VERSION 5.7 ;
  NOWIREEXTENSIONATPIN ON ;
  DIVIDERCHAR "/" ;
  BUSBITCHARS "[]" ;
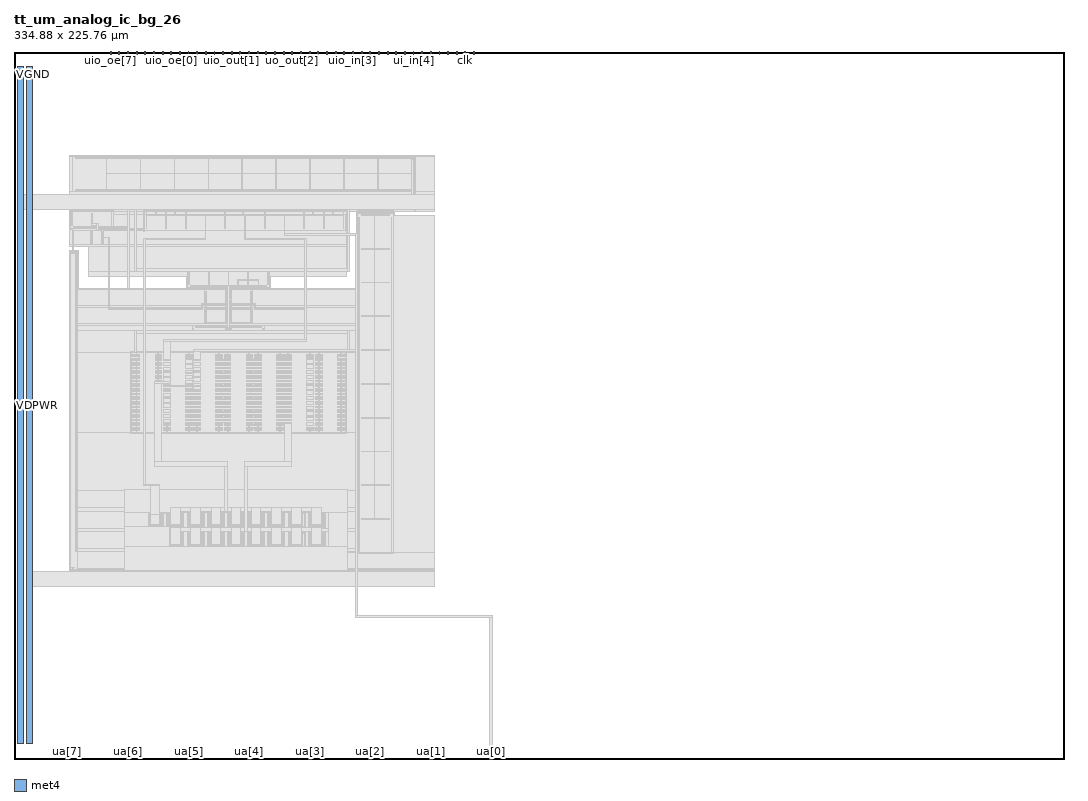
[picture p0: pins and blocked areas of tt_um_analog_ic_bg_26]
MACRO tt_um_analog_ic_bg_26
  CLASS BLOCK ;
  FOREIGN tt_um_analog_ic_bg_26 ;
  ORIGIN 0.000 0.000 ;
  SIZE 334.880 BY 225.760 ;
  PIN clk
    PORT
      LAYER met4 ;
        RECT 143.830 224.760 144.130 225.760 ;
    END
  END clk
  PIN ena
    PORT
      LAYER met4 ;
        RECT 146.590 224.760 146.890 225.760 ;
    END
  END ena
  PIN rst_n
    PORT
      LAYER met4 ;
        RECT 141.070 224.760 141.370 225.760 ;
    END
  END rst_n
  PIN ua[0]
    ANTENNADIFFAREA 1.160000 ;
    PORT
      LAYER met4 ;
        RECT 151.810 0.000 152.710 1.000 ;
    END
  END ua[0]
  PIN ua[1]
    PORT
      LAYER met4 ;
        RECT 132.490 0.000 133.390 1.000 ;
    END
  END ua[1]
  PIN ua[2]
    PORT
      LAYER met4 ;
        RECT 113.170 0.000 114.070 1.000 ;
    END
  END ua[2]
  PIN ua[3]
    PORT
      LAYER met4 ;
        RECT 93.850 0.000 94.750 1.000 ;
    END
  END ua[3]
  PIN ua[4]
    PORT
      LAYER met4 ;
        RECT 74.530 0.000 75.430 1.000 ;
    END
  END ua[4]
  PIN ua[5]
    PORT
      LAYER met4 ;
        RECT 55.210 0.000 56.110 1.000 ;
    END
  END ua[5]
  PIN ua[6]
    PORT
      LAYER met4 ;
        RECT 35.890 0.000 36.790 1.000 ;
    END
  END ua[6]
  PIN ua[7]
    PORT
      LAYER met4 ;
        RECT 16.570 0.000 17.470 1.000 ;
    END
  END ua[7]
  PIN ui_in[0]
    PORT
      LAYER met4 ;
        RECT 138.310 224.760 138.610 225.760 ;
    END
  END ui_in[0]
  PIN ui_in[1]
    PORT
      LAYER met4 ;
        RECT 135.550 224.760 135.850 225.760 ;
    END
  END ui_in[1]
  PIN ui_in[2]
    PORT
      LAYER met4 ;
        RECT 132.790 224.760 133.090 225.760 ;
    END
  END ui_in[2]
  PIN ui_in[3]
    PORT
      LAYER met4 ;
        RECT 130.030 224.760 130.330 225.760 ;
    END
  END ui_in[3]
  PIN ui_in[4]
    PORT
      LAYER met4 ;
        RECT 127.270 224.760 127.570 225.760 ;
    END
  END ui_in[4]
  PIN ui_in[5]
    PORT
      LAYER met4 ;
        RECT 124.510 224.760 124.810 225.760 ;
    END
  END ui_in[5]
  PIN ui_in[6]
    PORT
      LAYER met4 ;
        RECT 121.750 224.760 122.050 225.760 ;
    END
  END ui_in[6]
  PIN ui_in[7]
    PORT
      LAYER met4 ;
        RECT 118.990 224.760 119.290 225.760 ;
    END
  END ui_in[7]
  PIN uio_in[0]
    PORT
      LAYER met4 ;
        RECT 116.230 224.760 116.530 225.760 ;
    END
  END uio_in[0]
  PIN uio_in[1]
    PORT
      LAYER met4 ;
        RECT 113.470 224.760 113.770 225.760 ;
    END
  END uio_in[1]
  PIN uio_in[2]
    PORT
      LAYER met4 ;
        RECT 110.710 224.760 111.010 225.760 ;
    END
  END uio_in[2]
  PIN uio_in[3]
    PORT
      LAYER met4 ;
        RECT 107.950 224.760 108.250 225.760 ;
    END
  END uio_in[3]
  PIN uio_in[4]
    PORT
      LAYER met4 ;
        RECT 105.190 224.760 105.490 225.760 ;
    END
  END uio_in[4]
  PIN uio_in[5]
    PORT
      LAYER met4 ;
        RECT 102.430 224.760 102.730 225.760 ;
    END
  END uio_in[5]
  PIN uio_in[6]
    PORT
      LAYER met4 ;
        RECT 99.670 224.760 99.970 225.760 ;
    END
  END uio_in[6]
  PIN uio_in[7]
    PORT
      LAYER met4 ;
        RECT 96.910 224.760 97.210 225.760 ;
    END
  END uio_in[7]
  PIN uio_oe[0]
    PORT
      LAYER met4 ;
        RECT 49.990 224.760 50.290 225.760 ;
    END
  END uio_oe[0]
  PIN uio_oe[1]
    PORT
      LAYER met4 ;
        RECT 47.230 224.760 47.530 225.760 ;
    END
  END uio_oe[1]
  PIN uio_oe[2]
    PORT
      LAYER met4 ;
        RECT 44.470 224.760 44.770 225.760 ;
    END
  END uio_oe[2]
  PIN uio_oe[3]
    PORT
      LAYER met4 ;
        RECT 41.710 224.760 42.010 225.760 ;
    END
  END uio_oe[3]
  PIN uio_oe[4]
    PORT
      LAYER met4 ;
        RECT 38.950 224.760 39.250 225.760 ;
    END
  END uio_oe[4]
  PIN uio_oe[5]
    PORT
      LAYER met4 ;
        RECT 36.190 224.760 36.490 225.760 ;
    END
  END uio_oe[5]
  PIN uio_oe[6]
    PORT
      LAYER met4 ;
        RECT 33.430 224.760 33.730 225.760 ;
    END
  END uio_oe[6]
  PIN uio_oe[7]
    PORT
      LAYER met4 ;
        RECT 30.670 224.760 30.970 225.760 ;
    END
  END uio_oe[7]
  PIN uio_out[0]
    PORT
      LAYER met4 ;
        RECT 72.070 224.760 72.370 225.760 ;
    END
  END uio_out[0]
  PIN uio_out[1]
    PORT
      LAYER met4 ;
        RECT 69.310 224.760 69.610 225.760 ;
    END
  END uio_out[1]
  PIN uio_out[2]
    PORT
      LAYER met4 ;
        RECT 66.550 224.760 66.850 225.760 ;
    END
  END uio_out[2]
  PIN uio_out[3]
    PORT
      LAYER met4 ;
        RECT 63.790 224.760 64.090 225.760 ;
    END
  END uio_out[3]
  PIN uio_out[4]
    PORT
      LAYER met4 ;
        RECT 61.030 224.760 61.330 225.760 ;
    END
  END uio_out[4]
  PIN uio_out[5]
    PORT
      LAYER met4 ;
        RECT 58.270 224.760 58.570 225.760 ;
    END
  END uio_out[5]
  PIN uio_out[6]
    PORT
      LAYER met4 ;
        RECT 55.510 224.760 55.810 225.760 ;
    END
  END uio_out[6]
  PIN uio_out[7]
    PORT
      LAYER met4 ;
        RECT 52.750 224.760 53.050 225.760 ;
    END
  END uio_out[7]
  PIN uo_out[0]
    PORT
      LAYER met4 ;
        RECT 94.150 224.760 94.450 225.760 ;
    END
  END uo_out[0]
  PIN uo_out[1]
    PORT
      LAYER met4 ;
        RECT 91.390 224.760 91.690 225.760 ;
    END
  END uo_out[1]
  PIN uo_out[2]
    PORT
      LAYER met4 ;
        RECT 88.630 224.760 88.930 225.760 ;
    END
  END uo_out[2]
  PIN uo_out[3]
    PORT
      LAYER met4 ;
        RECT 85.870 224.760 86.170 225.760 ;
    END
  END uo_out[3]
  PIN uo_out[4]
    PORT
      LAYER met4 ;
        RECT 83.110 224.760 83.410 225.760 ;
    END
  END uo_out[4]
  PIN uo_out[5]
    PORT
      LAYER met4 ;
        RECT 80.350 224.760 80.650 225.760 ;
    END
  END uo_out[5]
  PIN uo_out[6]
    PORT
      LAYER met4 ;
        RECT 77.590 224.760 77.890 225.760 ;
    END
  END uo_out[6]
  PIN uo_out[7]
    PORT
      LAYER met4 ;
        RECT 74.830 224.760 75.130 225.760 ;
    END
  END uo_out[7]
  PIN VDPWR
    DIRECTION INOUT ;
    USE POWER ;
    PORT
      LAYER met4 ;
        RECT 1.000 5.000 3.000 220.760 ;
    END
  END VDPWR
  PIN VGND
    DIRECTION INOUT ;
    USE GROUND ;
    PORT
      LAYER met4 ;
        RECT 4.000 5.000 6.000 220.760 ;
    END
  END VGND
  OBS
      LAYER nwell ;
        RECT 18.460 180.585 127.720 192.545 ;
        RECT 17.680 168.980 31.930 174.820 ;
        RECT 22.360 168.775 28.935 168.980 ;
        RECT 23.975 163.530 28.935 168.775 ;
        RECT 41.385 168.320 105.955 174.160 ;
      LAYER pwell ;
        RECT 17.680 60.235 20.470 162.195 ;
      LAYER nwell ;
        RECT 54.990 150.080 81.820 155.920 ;
      LAYER pwell ;
        RECT 60.440 138.500 76.360 150.080 ;
        RECT 56.440 136.210 80.360 138.500 ;
        RECT 37.165 103.795 106.065 129.875 ;
        RECT 35.245 85.375 106.345 86.140 ;
        RECT 35.245 80.205 36.010 85.375 ;
        RECT 41.180 80.205 42.450 85.375 ;
        RECT 47.620 80.205 48.890 85.375 ;
        RECT 54.060 80.205 55.330 85.375 ;
        RECT 60.500 80.205 61.770 85.375 ;
        RECT 66.940 80.205 68.210 85.375 ;
        RECT 73.380 80.205 74.650 85.375 ;
        RECT 79.820 80.205 81.090 85.375 ;
        RECT 86.260 80.205 87.530 85.375 ;
        RECT 92.700 80.205 93.970 85.375 ;
        RECT 99.140 80.205 100.410 85.375 ;
        RECT 105.580 80.205 106.345 85.375 ;
        RECT 35.245 78.935 106.345 80.205 ;
        RECT 35.245 73.765 36.010 78.935 ;
        RECT 41.180 73.765 42.450 78.935 ;
        RECT 47.620 73.765 48.890 78.935 ;
        RECT 54.060 73.765 55.330 78.935 ;
        RECT 60.500 73.765 61.770 78.935 ;
        RECT 66.940 73.765 68.210 78.935 ;
        RECT 73.380 73.765 74.650 78.935 ;
        RECT 79.820 73.765 81.090 78.935 ;
        RECT 86.260 73.765 87.530 78.935 ;
        RECT 92.700 73.765 93.970 78.935 ;
        RECT 99.140 73.765 100.410 78.935 ;
        RECT 105.580 73.765 106.345 78.935 ;
        RECT 35.245 72.495 106.345 73.765 ;
        RECT 35.245 67.325 36.010 72.495 ;
        RECT 41.180 67.325 42.450 72.495 ;
        RECT 47.620 67.325 48.890 72.495 ;
        RECT 54.060 67.325 55.330 72.495 ;
        RECT 60.500 67.325 61.770 72.495 ;
        RECT 66.940 67.325 68.210 72.495 ;
        RECT 73.380 67.325 74.650 72.495 ;
        RECT 79.820 67.325 81.090 72.495 ;
        RECT 86.260 67.325 87.530 72.495 ;
        RECT 92.700 67.325 93.970 72.495 ;
        RECT 99.140 67.325 100.410 72.495 ;
        RECT 105.580 67.325 106.345 72.495 ;
        RECT 35.245 66.055 106.345 67.325 ;
        RECT 35.245 60.885 36.010 66.055 ;
        RECT 41.180 60.885 42.450 66.055 ;
        RECT 47.620 60.885 48.890 66.055 ;
        RECT 54.060 60.885 55.330 66.055 ;
        RECT 60.500 60.885 61.770 66.055 ;
        RECT 66.940 60.885 68.210 66.055 ;
        RECT 73.380 60.885 74.650 66.055 ;
        RECT 79.820 60.885 81.090 66.055 ;
        RECT 86.260 60.885 87.530 66.055 ;
        RECT 92.700 60.885 93.970 66.055 ;
        RECT 99.140 60.885 100.410 66.055 ;
        RECT 105.580 60.885 106.345 66.055 ;
        RECT 109.270 65.505 121.230 174.315 ;
        RECT 35.245 60.120 106.345 60.885 ;
      LAYER li1 ;
        RECT 17.680 192.195 134.130 192.545 ;
        RECT 17.680 180.935 18.810 192.195 ;
        RECT 19.675 191.625 28.725 191.795 ;
        RECT 30.500 191.625 39.550 191.795 ;
        RECT 41.325 191.625 50.375 191.795 ;
        RECT 52.150 191.625 61.200 191.795 ;
        RECT 62.975 191.625 72.025 191.795 ;
        RECT 73.800 191.625 82.850 191.795 ;
        RECT 84.625 191.625 93.675 191.795 ;
        RECT 95.450 191.625 104.500 191.795 ;
        RECT 106.275 191.625 115.325 191.795 ;
        RECT 117.100 191.625 126.150 191.795 ;
        RECT 29.435 182.055 29.605 191.075 ;
        RECT 40.260 182.055 40.430 191.075 ;
        RECT 51.085 182.055 51.255 191.075 ;
        RECT 61.910 182.055 62.080 191.075 ;
        RECT 72.735 182.055 72.905 191.075 ;
        RECT 83.560 182.055 83.730 191.075 ;
        RECT 94.385 182.055 94.555 191.075 ;
        RECT 105.210 182.055 105.380 191.075 ;
        RECT 116.035 182.055 116.205 191.075 ;
        RECT 126.860 182.055 127.030 191.075 ;
        RECT 19.675 181.335 28.725 181.505 ;
        RECT 30.500 181.335 39.550 181.505 ;
        RECT 41.325 181.335 50.375 181.505 ;
        RECT 52.150 181.335 61.200 181.505 ;
        RECT 62.975 181.335 72.025 181.505 ;
        RECT 73.800 181.335 82.850 181.505 ;
        RECT 84.625 181.335 93.675 181.505 ;
        RECT 95.450 181.335 104.500 181.505 ;
        RECT 106.275 181.335 115.325 181.505 ;
        RECT 117.100 181.335 126.150 181.505 ;
        RECT 127.370 180.935 134.130 192.195 ;
        RECT 17.680 174.470 134.130 180.935 ;
        RECT 17.680 169.330 18.030 174.470 ;
        RECT 18.430 170.255 18.600 173.905 ;
        RECT 24.720 170.255 24.890 173.905 ;
        RECT 31.010 170.255 31.180 173.905 ;
        RECT 31.580 173.810 105.955 174.470 ;
        RECT 18.950 169.675 24.370 169.845 ;
        RECT 25.240 169.675 30.660 169.845 ;
        RECT 31.580 169.330 41.735 173.810 ;
        RECT 42.655 173.295 48.075 173.465 ;
        RECT 48.945 173.295 54.365 173.465 ;
        RECT 55.235 173.295 60.655 173.465 ;
        RECT 61.525 173.295 66.945 173.465 ;
        RECT 67.815 173.295 73.235 173.465 ;
        RECT 74.105 173.295 79.525 173.465 ;
        RECT 80.395 173.295 85.815 173.465 ;
        RECT 86.685 173.295 92.105 173.465 ;
        RECT 92.975 173.295 98.395 173.465 ;
        RECT 99.265 173.295 104.685 173.465 ;
        RECT 17.680 169.020 41.735 169.330 ;
        RECT 42.135 169.235 42.305 172.885 ;
        RECT 48.425 169.235 48.595 172.885 ;
        RECT 54.715 169.235 54.885 172.885 ;
        RECT 61.005 169.235 61.175 172.885 ;
        RECT 67.295 169.235 67.465 172.885 ;
        RECT 73.585 169.235 73.755 172.885 ;
        RECT 79.875 169.235 80.045 172.885 ;
        RECT 86.165 169.235 86.335 172.885 ;
        RECT 92.455 169.235 92.625 172.885 ;
        RECT 98.745 169.235 98.915 172.885 ;
        RECT 105.035 169.235 105.205 172.885 ;
        RECT 17.680 163.950 24.325 169.020 ;
        RECT 25.095 168.505 27.815 168.675 ;
        RECT 28.585 168.670 41.735 169.020 ;
        RECT 105.605 168.670 105.955 173.810 ;
        RECT 24.725 164.445 24.895 168.095 ;
        RECT 28.015 164.445 28.185 168.095 ;
        RECT 28.585 163.950 105.955 168.670 ;
        RECT 17.680 163.530 105.955 163.950 ;
        RECT 20.120 162.015 20.470 162.195 ;
        RECT 17.860 161.845 20.470 162.015 ;
        RECT 17.860 60.595 18.030 161.845 ;
        RECT 18.445 161.275 19.395 161.445 ;
        RECT 19.610 66.205 19.780 156.225 ;
        RECT 20.120 149.900 20.470 161.845 ;
        RECT 23.915 155.570 105.955 163.530 ;
        RECT 23.915 153.955 55.340 155.570 ;
        RECT 55.170 150.430 55.340 153.955 ;
        RECT 55.740 151.355 55.910 155.005 ;
        RECT 62.030 151.355 62.200 155.005 ;
        RECT 68.320 151.355 68.490 155.005 ;
        RECT 74.610 151.355 74.780 155.005 ;
        RECT 80.900 151.355 81.070 155.005 ;
        RECT 81.470 153.955 105.955 155.570 ;
        RECT 109.450 173.965 121.050 174.150 ;
        RECT 56.260 150.775 61.680 150.945 ;
        RECT 62.550 150.775 67.970 150.945 ;
        RECT 68.840 150.775 74.260 150.945 ;
        RECT 75.130 150.775 80.550 150.945 ;
        RECT 81.470 150.430 81.640 153.955 ;
        RECT 55.170 150.260 81.640 150.430 ;
        RECT 109.450 149.900 109.620 173.965 ;
        RECT 110.740 173.455 119.760 173.625 ;
        RECT 120.880 173.205 121.050 173.965 ;
        RECT 110.020 163.740 110.190 172.790 ;
        RECT 120.310 163.740 120.480 172.790 ;
        RECT 110.740 162.675 119.760 162.845 ;
        RECT 110.020 152.960 110.190 162.010 ;
        RECT 120.310 152.960 120.480 162.010 ;
        RECT 110.740 151.895 119.760 152.065 ;
        RECT 20.120 149.730 109.620 149.900 ;
        RECT 20.120 144.640 60.790 149.730 ;
        RECT 61.190 145.515 61.360 149.165 ;
        RECT 67.480 145.515 67.650 149.165 ;
        RECT 61.710 144.980 67.130 145.150 ;
        RECT 68.050 144.640 68.750 149.730 ;
        RECT 69.150 145.515 69.320 149.165 ;
        RECT 75.440 145.515 75.610 149.165 ;
        RECT 69.670 144.980 75.090 145.150 ;
        RECT 76.010 144.640 109.620 149.730 ;
        RECT 20.120 143.940 109.620 144.640 ;
        RECT 20.120 138.850 60.790 143.940 ;
        RECT 61.710 143.430 67.130 143.600 ;
        RECT 61.190 139.415 61.360 143.065 ;
        RECT 67.480 139.415 67.650 143.065 ;
        RECT 68.050 138.850 68.750 143.940 ;
        RECT 69.670 143.430 75.090 143.600 ;
        RECT 69.150 139.415 69.320 143.065 ;
        RECT 75.440 139.415 75.610 143.065 ;
        RECT 76.010 138.850 109.620 143.940 ;
        RECT 110.020 142.180 110.190 151.230 ;
        RECT 120.310 142.180 120.480 151.230 ;
        RECT 110.740 141.115 119.760 141.285 ;
        RECT 20.120 138.150 109.620 138.850 ;
        RECT 20.120 136.560 56.790 138.150 ;
        RECT 57.910 137.640 66.930 137.810 ;
        RECT 57.190 136.950 57.360 137.450 ;
        RECT 67.480 136.950 67.650 137.450 ;
        RECT 68.050 136.560 68.750 138.150 ;
        RECT 69.870 137.640 78.890 137.810 ;
        RECT 69.150 136.950 69.320 137.450 ;
        RECT 79.440 136.950 79.610 137.450 ;
        RECT 80.010 136.560 109.620 138.150 ;
        RECT 20.120 129.525 109.620 136.560 ;
        RECT 110.020 131.400 110.190 140.450 ;
        RECT 120.310 131.400 120.480 140.450 ;
        RECT 110.740 130.335 119.760 130.505 ;
        RECT 20.120 104.145 37.520 129.525 ;
        RECT 37.995 128.695 40.155 129.045 ;
        RECT 44.995 128.695 47.155 129.045 ;
        RECT 47.675 128.695 49.835 129.045 ;
        RECT 54.675 128.695 56.835 129.045 ;
        RECT 57.355 128.695 59.515 129.045 ;
        RECT 64.355 128.695 66.515 129.045 ;
        RECT 67.035 128.695 69.195 129.045 ;
        RECT 74.035 128.695 76.195 129.045 ;
        RECT 76.715 128.695 78.875 129.045 ;
        RECT 83.715 128.695 85.875 129.045 ;
        RECT 86.395 128.695 88.555 129.045 ;
        RECT 93.395 128.695 95.555 129.045 ;
        RECT 96.075 128.695 98.235 129.045 ;
        RECT 103.075 128.695 105.235 129.045 ;
        RECT 37.995 127.865 40.155 128.215 ;
        RECT 44.995 127.865 47.155 128.215 ;
        RECT 47.675 127.865 49.835 128.215 ;
        RECT 54.675 127.865 56.835 128.215 ;
        RECT 57.355 127.865 59.515 128.215 ;
        RECT 64.355 127.865 66.515 128.215 ;
        RECT 67.035 127.865 69.195 128.215 ;
        RECT 74.035 127.865 76.195 128.215 ;
        RECT 76.715 127.865 78.875 128.215 ;
        RECT 83.715 127.865 85.875 128.215 ;
        RECT 86.395 127.865 88.555 128.215 ;
        RECT 93.395 127.865 95.555 128.215 ;
        RECT 96.075 127.865 98.235 128.215 ;
        RECT 103.075 127.865 105.235 128.215 ;
        RECT 37.995 127.035 40.155 127.385 ;
        RECT 44.995 127.035 47.155 127.385 ;
        RECT 47.675 127.035 49.835 127.385 ;
        RECT 54.675 127.035 56.835 127.385 ;
        RECT 57.355 127.035 59.515 127.385 ;
        RECT 64.355 127.035 66.515 127.385 ;
        RECT 67.035 127.035 69.195 127.385 ;
        RECT 74.035 127.035 76.195 127.385 ;
        RECT 76.715 127.035 78.875 127.385 ;
        RECT 83.715 127.035 85.875 127.385 ;
        RECT 86.395 127.035 88.555 127.385 ;
        RECT 93.395 127.035 95.555 127.385 ;
        RECT 96.075 127.035 98.235 127.385 ;
        RECT 103.075 127.035 105.235 127.385 ;
        RECT 37.995 126.205 40.155 126.555 ;
        RECT 44.995 126.205 47.155 126.555 ;
        RECT 47.675 126.205 49.835 126.555 ;
        RECT 54.675 126.205 56.835 126.555 ;
        RECT 57.355 126.205 59.515 126.555 ;
        RECT 64.355 126.205 66.515 126.555 ;
        RECT 67.035 126.205 69.195 126.555 ;
        RECT 74.035 126.205 76.195 126.555 ;
        RECT 76.715 126.205 78.875 126.555 ;
        RECT 83.715 126.205 85.875 126.555 ;
        RECT 86.395 126.205 88.555 126.555 ;
        RECT 93.395 126.205 95.555 126.555 ;
        RECT 96.075 126.205 98.235 126.555 ;
        RECT 103.075 126.205 105.235 126.555 ;
        RECT 37.995 125.375 40.155 125.725 ;
        RECT 44.995 125.375 47.155 125.725 ;
        RECT 47.675 125.375 49.835 125.725 ;
        RECT 54.675 125.375 56.835 125.725 ;
        RECT 57.355 125.375 59.515 125.725 ;
        RECT 64.355 125.375 66.515 125.725 ;
        RECT 67.035 125.375 69.195 125.725 ;
        RECT 74.035 125.375 76.195 125.725 ;
        RECT 76.715 125.375 78.875 125.725 ;
        RECT 83.715 125.375 85.875 125.725 ;
        RECT 86.395 125.375 88.555 125.725 ;
        RECT 93.395 125.375 95.555 125.725 ;
        RECT 96.075 125.375 98.235 125.725 ;
        RECT 103.075 125.375 105.235 125.725 ;
        RECT 37.995 124.545 40.155 124.895 ;
        RECT 44.995 124.545 47.155 124.895 ;
        RECT 47.675 124.545 49.835 124.895 ;
        RECT 54.675 124.545 56.835 124.895 ;
        RECT 57.355 124.545 59.515 124.895 ;
        RECT 64.355 124.545 66.515 124.895 ;
        RECT 67.035 124.545 69.195 124.895 ;
        RECT 74.035 124.545 76.195 124.895 ;
        RECT 76.715 124.545 78.875 124.895 ;
        RECT 83.715 124.545 85.875 124.895 ;
        RECT 86.395 124.545 88.555 124.895 ;
        RECT 93.395 124.545 95.555 124.895 ;
        RECT 96.075 124.545 98.235 124.895 ;
        RECT 103.075 124.545 105.235 124.895 ;
        RECT 37.995 123.715 40.155 124.065 ;
        RECT 44.995 123.715 47.155 124.065 ;
        RECT 47.675 123.715 49.835 124.065 ;
        RECT 54.675 123.715 56.835 124.065 ;
        RECT 57.355 123.715 59.515 124.065 ;
        RECT 64.355 123.715 66.515 124.065 ;
        RECT 67.035 123.715 69.195 124.065 ;
        RECT 74.035 123.715 76.195 124.065 ;
        RECT 76.715 123.715 78.875 124.065 ;
        RECT 83.715 123.715 85.875 124.065 ;
        RECT 86.395 123.715 88.555 124.065 ;
        RECT 93.395 123.715 95.555 124.065 ;
        RECT 96.075 123.715 98.235 124.065 ;
        RECT 103.075 123.715 105.235 124.065 ;
        RECT 37.995 122.885 40.155 123.235 ;
        RECT 44.995 122.885 47.155 123.235 ;
        RECT 47.675 122.885 49.835 123.235 ;
        RECT 54.675 122.885 56.835 123.235 ;
        RECT 57.355 122.885 59.515 123.235 ;
        RECT 64.355 122.885 66.515 123.235 ;
        RECT 67.035 122.885 69.195 123.235 ;
        RECT 74.035 122.885 76.195 123.235 ;
        RECT 76.715 122.885 78.875 123.235 ;
        RECT 83.715 122.885 85.875 123.235 ;
        RECT 86.395 122.885 88.555 123.235 ;
        RECT 93.395 122.885 95.555 123.235 ;
        RECT 96.075 122.885 98.235 123.235 ;
        RECT 103.075 122.885 105.235 123.235 ;
        RECT 37.995 122.055 40.155 122.405 ;
        RECT 44.995 122.055 47.155 122.405 ;
        RECT 47.675 122.055 49.835 122.405 ;
        RECT 54.675 122.055 56.835 122.405 ;
        RECT 57.355 122.055 59.515 122.405 ;
        RECT 64.355 122.055 66.515 122.405 ;
        RECT 67.035 122.055 69.195 122.405 ;
        RECT 74.035 122.055 76.195 122.405 ;
        RECT 76.715 122.055 78.875 122.405 ;
        RECT 83.715 122.055 85.875 122.405 ;
        RECT 86.395 122.055 88.555 122.405 ;
        RECT 93.395 122.055 95.555 122.405 ;
        RECT 96.075 122.055 98.235 122.405 ;
        RECT 103.075 122.055 105.235 122.405 ;
        RECT 37.995 121.225 40.155 121.575 ;
        RECT 44.995 121.225 47.155 121.575 ;
        RECT 47.675 121.225 49.835 121.575 ;
        RECT 54.675 121.225 56.835 121.575 ;
        RECT 57.355 121.225 59.515 121.575 ;
        RECT 64.355 121.225 66.515 121.575 ;
        RECT 67.035 121.225 69.195 121.575 ;
        RECT 74.035 121.225 76.195 121.575 ;
        RECT 76.715 121.225 78.875 121.575 ;
        RECT 83.715 121.225 85.875 121.575 ;
        RECT 86.395 121.225 88.555 121.575 ;
        RECT 93.395 121.225 95.555 121.575 ;
        RECT 96.075 121.225 98.235 121.575 ;
        RECT 103.075 121.225 105.235 121.575 ;
        RECT 37.995 120.395 40.155 120.745 ;
        RECT 44.995 120.395 47.155 120.745 ;
        RECT 47.675 120.395 49.835 120.745 ;
        RECT 54.675 120.395 56.835 120.745 ;
        RECT 57.355 120.395 59.515 120.745 ;
        RECT 64.355 120.395 66.515 120.745 ;
        RECT 67.035 120.395 69.195 120.745 ;
        RECT 74.035 120.395 76.195 120.745 ;
        RECT 76.715 120.395 78.875 120.745 ;
        RECT 83.715 120.395 85.875 120.745 ;
        RECT 86.395 120.395 88.555 120.745 ;
        RECT 93.395 120.395 95.555 120.745 ;
        RECT 96.075 120.395 98.235 120.745 ;
        RECT 103.075 120.395 105.235 120.745 ;
        RECT 37.995 119.565 40.155 119.915 ;
        RECT 44.995 119.565 47.155 119.915 ;
        RECT 47.675 119.565 49.835 119.915 ;
        RECT 54.675 119.565 56.835 119.915 ;
        RECT 57.355 119.565 59.515 119.915 ;
        RECT 64.355 119.565 66.515 119.915 ;
        RECT 67.035 119.565 69.195 119.915 ;
        RECT 74.035 119.565 76.195 119.915 ;
        RECT 76.715 119.565 78.875 119.915 ;
        RECT 83.715 119.565 85.875 119.915 ;
        RECT 86.395 119.565 88.555 119.915 ;
        RECT 93.395 119.565 95.555 119.915 ;
        RECT 96.075 119.565 98.235 119.915 ;
        RECT 103.075 119.565 105.235 119.915 ;
        RECT 37.995 118.735 40.155 119.085 ;
        RECT 44.995 118.735 47.155 119.085 ;
        RECT 47.675 118.735 49.835 119.085 ;
        RECT 54.675 118.735 56.835 119.085 ;
        RECT 57.355 118.735 59.515 119.085 ;
        RECT 64.355 118.735 66.515 119.085 ;
        RECT 67.035 118.735 69.195 119.085 ;
        RECT 74.035 118.735 76.195 119.085 ;
        RECT 76.715 118.735 78.875 119.085 ;
        RECT 83.715 118.735 85.875 119.085 ;
        RECT 86.395 118.735 88.555 119.085 ;
        RECT 93.395 118.735 95.555 119.085 ;
        RECT 96.075 118.735 98.235 119.085 ;
        RECT 103.075 118.735 105.235 119.085 ;
        RECT 37.995 117.905 40.155 118.255 ;
        RECT 44.995 117.905 47.155 118.255 ;
        RECT 47.675 117.905 49.835 118.255 ;
        RECT 54.675 117.905 56.835 118.255 ;
        RECT 57.355 117.905 59.515 118.255 ;
        RECT 64.355 117.905 66.515 118.255 ;
        RECT 67.035 117.905 69.195 118.255 ;
        RECT 74.035 117.905 76.195 118.255 ;
        RECT 76.715 117.905 78.875 118.255 ;
        RECT 83.715 117.905 85.875 118.255 ;
        RECT 86.395 117.905 88.555 118.255 ;
        RECT 93.395 117.905 95.555 118.255 ;
        RECT 96.075 117.905 98.235 118.255 ;
        RECT 103.075 117.905 105.235 118.255 ;
        RECT 37.995 117.075 40.155 117.425 ;
        RECT 44.995 117.075 47.155 117.425 ;
        RECT 47.675 117.075 49.835 117.425 ;
        RECT 54.675 117.075 56.835 117.425 ;
        RECT 57.355 117.075 59.515 117.425 ;
        RECT 64.355 117.075 66.515 117.425 ;
        RECT 67.035 117.075 69.195 117.425 ;
        RECT 74.035 117.075 76.195 117.425 ;
        RECT 76.715 117.075 78.875 117.425 ;
        RECT 83.715 117.075 85.875 117.425 ;
        RECT 86.395 117.075 88.555 117.425 ;
        RECT 93.395 117.075 95.555 117.425 ;
        RECT 96.075 117.075 98.235 117.425 ;
        RECT 103.075 117.075 105.235 117.425 ;
        RECT 37.995 116.245 40.155 116.595 ;
        RECT 44.995 116.245 47.155 116.595 ;
        RECT 47.675 116.245 49.835 116.595 ;
        RECT 54.675 116.245 56.835 116.595 ;
        RECT 57.355 116.245 59.515 116.595 ;
        RECT 64.355 116.245 66.515 116.595 ;
        RECT 67.035 116.245 69.195 116.595 ;
        RECT 74.035 116.245 76.195 116.595 ;
        RECT 76.715 116.245 78.875 116.595 ;
        RECT 83.715 116.245 85.875 116.595 ;
        RECT 86.395 116.245 88.555 116.595 ;
        RECT 93.395 116.245 95.555 116.595 ;
        RECT 96.075 116.245 98.235 116.595 ;
        RECT 103.075 116.245 105.235 116.595 ;
        RECT 37.995 115.415 40.155 115.765 ;
        RECT 44.995 115.415 47.155 115.765 ;
        RECT 47.675 115.415 49.835 115.765 ;
        RECT 54.675 115.415 56.835 115.765 ;
        RECT 57.355 115.415 59.515 115.765 ;
        RECT 64.355 115.415 66.515 115.765 ;
        RECT 67.035 115.415 69.195 115.765 ;
        RECT 74.035 115.415 76.195 115.765 ;
        RECT 76.715 115.415 78.875 115.765 ;
        RECT 83.715 115.415 85.875 115.765 ;
        RECT 86.395 115.415 88.555 115.765 ;
        RECT 93.395 115.415 95.555 115.765 ;
        RECT 96.075 115.415 98.235 115.765 ;
        RECT 103.075 115.415 105.235 115.765 ;
        RECT 37.995 114.585 40.155 114.935 ;
        RECT 44.995 114.585 47.155 114.935 ;
        RECT 47.675 114.585 49.835 114.935 ;
        RECT 54.675 114.585 56.835 114.935 ;
        RECT 57.355 114.585 59.515 114.935 ;
        RECT 64.355 114.585 66.515 114.935 ;
        RECT 67.035 114.585 69.195 114.935 ;
        RECT 74.035 114.585 76.195 114.935 ;
        RECT 76.715 114.585 78.875 114.935 ;
        RECT 83.715 114.585 85.875 114.935 ;
        RECT 86.395 114.585 88.555 114.935 ;
        RECT 93.395 114.585 95.555 114.935 ;
        RECT 96.075 114.585 98.235 114.935 ;
        RECT 103.075 114.585 105.235 114.935 ;
        RECT 37.995 113.755 40.155 114.105 ;
        RECT 44.995 113.755 47.155 114.105 ;
        RECT 47.675 113.755 49.835 114.105 ;
        RECT 54.675 113.755 56.835 114.105 ;
        RECT 57.355 113.755 59.515 114.105 ;
        RECT 64.355 113.755 66.515 114.105 ;
        RECT 67.035 113.755 69.195 114.105 ;
        RECT 74.035 113.755 76.195 114.105 ;
        RECT 76.715 113.755 78.875 114.105 ;
        RECT 83.715 113.755 85.875 114.105 ;
        RECT 86.395 113.755 88.555 114.105 ;
        RECT 93.395 113.755 95.555 114.105 ;
        RECT 96.075 113.755 98.235 114.105 ;
        RECT 103.075 113.755 105.235 114.105 ;
        RECT 37.995 112.925 40.155 113.275 ;
        RECT 44.995 112.925 47.155 113.275 ;
        RECT 47.675 112.925 49.835 113.275 ;
        RECT 54.675 112.925 56.835 113.275 ;
        RECT 57.355 112.925 59.515 113.275 ;
        RECT 64.355 112.925 66.515 113.275 ;
        RECT 67.035 112.925 69.195 113.275 ;
        RECT 74.035 112.925 76.195 113.275 ;
        RECT 76.715 112.925 78.875 113.275 ;
        RECT 83.715 112.925 85.875 113.275 ;
        RECT 86.395 112.925 88.555 113.275 ;
        RECT 93.395 112.925 95.555 113.275 ;
        RECT 96.075 112.925 98.235 113.275 ;
        RECT 103.075 112.925 105.235 113.275 ;
        RECT 37.995 112.095 40.155 112.445 ;
        RECT 44.995 112.095 47.155 112.445 ;
        RECT 47.675 112.095 49.835 112.445 ;
        RECT 54.675 112.095 56.835 112.445 ;
        RECT 57.355 112.095 59.515 112.445 ;
        RECT 64.355 112.095 66.515 112.445 ;
        RECT 67.035 112.095 69.195 112.445 ;
        RECT 74.035 112.095 76.195 112.445 ;
        RECT 76.715 112.095 78.875 112.445 ;
        RECT 83.715 112.095 85.875 112.445 ;
        RECT 86.395 112.095 88.555 112.445 ;
        RECT 93.395 112.095 95.555 112.445 ;
        RECT 96.075 112.095 98.235 112.445 ;
        RECT 103.075 112.095 105.235 112.445 ;
        RECT 37.995 111.265 40.155 111.615 ;
        RECT 44.995 111.265 47.155 111.615 ;
        RECT 47.675 111.265 49.835 111.615 ;
        RECT 54.675 111.265 56.835 111.615 ;
        RECT 57.355 111.265 59.515 111.615 ;
        RECT 64.355 111.265 66.515 111.615 ;
        RECT 67.035 111.265 69.195 111.615 ;
        RECT 74.035 111.265 76.195 111.615 ;
        RECT 76.715 111.265 78.875 111.615 ;
        RECT 83.715 111.265 85.875 111.615 ;
        RECT 86.395 111.265 88.555 111.615 ;
        RECT 93.395 111.265 95.555 111.615 ;
        RECT 96.075 111.265 98.235 111.615 ;
        RECT 103.075 111.265 105.235 111.615 ;
        RECT 37.995 110.435 40.155 110.785 ;
        RECT 44.995 110.435 47.155 110.785 ;
        RECT 47.675 110.435 49.835 110.785 ;
        RECT 54.675 110.435 56.835 110.785 ;
        RECT 57.355 110.435 59.515 110.785 ;
        RECT 64.355 110.435 66.515 110.785 ;
        RECT 67.035 110.435 69.195 110.785 ;
        RECT 74.035 110.435 76.195 110.785 ;
        RECT 76.715 110.435 78.875 110.785 ;
        RECT 83.715 110.435 85.875 110.785 ;
        RECT 86.395 110.435 88.555 110.785 ;
        RECT 93.395 110.435 95.555 110.785 ;
        RECT 96.075 110.435 98.235 110.785 ;
        RECT 103.075 110.435 105.235 110.785 ;
        RECT 37.995 109.605 40.155 109.955 ;
        RECT 44.995 109.605 47.155 109.955 ;
        RECT 47.675 109.605 49.835 109.955 ;
        RECT 54.675 109.605 56.835 109.955 ;
        RECT 57.355 109.605 59.515 109.955 ;
        RECT 64.355 109.605 66.515 109.955 ;
        RECT 67.035 109.605 69.195 109.955 ;
        RECT 74.035 109.605 76.195 109.955 ;
        RECT 76.715 109.605 78.875 109.955 ;
        RECT 83.715 109.605 85.875 109.955 ;
        RECT 86.395 109.605 88.555 109.955 ;
        RECT 93.395 109.605 95.555 109.955 ;
        RECT 96.075 109.605 98.235 109.955 ;
        RECT 103.075 109.605 105.235 109.955 ;
        RECT 37.995 108.775 40.155 109.125 ;
        RECT 44.995 108.775 47.155 109.125 ;
        RECT 47.675 108.775 49.835 109.125 ;
        RECT 54.675 108.775 56.835 109.125 ;
        RECT 57.355 108.775 59.515 109.125 ;
        RECT 64.355 108.775 66.515 109.125 ;
        RECT 67.035 108.775 69.195 109.125 ;
        RECT 74.035 108.775 76.195 109.125 ;
        RECT 76.715 108.775 78.875 109.125 ;
        RECT 83.715 108.775 85.875 109.125 ;
        RECT 86.395 108.775 88.555 109.125 ;
        RECT 93.395 108.775 95.555 109.125 ;
        RECT 96.075 108.775 98.235 109.125 ;
        RECT 103.075 108.775 105.235 109.125 ;
        RECT 37.995 107.945 40.155 108.295 ;
        RECT 44.995 107.945 47.155 108.295 ;
        RECT 47.675 107.945 49.835 108.295 ;
        RECT 54.675 107.945 56.835 108.295 ;
        RECT 57.355 107.945 59.515 108.295 ;
        RECT 64.355 107.945 66.515 108.295 ;
        RECT 67.035 107.945 69.195 108.295 ;
        RECT 74.035 107.945 76.195 108.295 ;
        RECT 76.715 107.945 78.875 108.295 ;
        RECT 83.715 107.945 85.875 108.295 ;
        RECT 86.395 107.945 88.555 108.295 ;
        RECT 93.395 107.945 95.555 108.295 ;
        RECT 96.075 107.945 98.235 108.295 ;
        RECT 103.075 107.945 105.235 108.295 ;
        RECT 37.995 107.115 40.155 107.465 ;
        RECT 44.995 107.115 47.155 107.465 ;
        RECT 47.675 107.115 49.835 107.465 ;
        RECT 54.675 107.115 56.835 107.465 ;
        RECT 57.355 107.115 59.515 107.465 ;
        RECT 64.355 107.115 66.515 107.465 ;
        RECT 67.035 107.115 69.195 107.465 ;
        RECT 74.035 107.115 76.195 107.465 ;
        RECT 76.715 107.115 78.875 107.465 ;
        RECT 83.715 107.115 85.875 107.465 ;
        RECT 86.395 107.115 88.555 107.465 ;
        RECT 93.395 107.115 95.555 107.465 ;
        RECT 96.075 107.115 98.235 107.465 ;
        RECT 103.075 107.115 105.235 107.465 ;
        RECT 37.995 106.285 40.155 106.635 ;
        RECT 44.995 106.285 47.155 106.635 ;
        RECT 47.675 106.285 49.835 106.635 ;
        RECT 54.675 106.285 56.835 106.635 ;
        RECT 57.355 106.285 59.515 106.635 ;
        RECT 64.355 106.285 66.515 106.635 ;
        RECT 67.035 106.285 69.195 106.635 ;
        RECT 74.035 106.285 76.195 106.635 ;
        RECT 76.715 106.285 78.875 106.635 ;
        RECT 83.715 106.285 85.875 106.635 ;
        RECT 86.395 106.285 88.555 106.635 ;
        RECT 93.395 106.285 95.555 106.635 ;
        RECT 96.075 106.285 98.235 106.635 ;
        RECT 103.075 106.285 105.235 106.635 ;
        RECT 37.995 105.455 40.155 105.805 ;
        RECT 44.995 105.455 47.155 105.805 ;
        RECT 47.675 105.455 49.835 105.805 ;
        RECT 54.675 105.455 56.835 105.805 ;
        RECT 57.355 105.455 59.515 105.805 ;
        RECT 64.355 105.455 66.515 105.805 ;
        RECT 67.035 105.455 69.195 105.805 ;
        RECT 74.035 105.455 76.195 105.805 ;
        RECT 76.715 105.455 78.875 105.805 ;
        RECT 83.715 105.455 85.875 105.805 ;
        RECT 86.395 105.455 88.555 105.805 ;
        RECT 93.395 105.455 95.555 105.805 ;
        RECT 96.075 105.455 98.235 105.805 ;
        RECT 103.075 105.455 105.235 105.805 ;
        RECT 37.995 104.625 40.155 104.975 ;
        RECT 44.995 104.625 47.155 104.975 ;
        RECT 47.675 104.625 49.835 104.975 ;
        RECT 54.675 104.625 56.835 104.975 ;
        RECT 57.355 104.625 59.515 104.975 ;
        RECT 64.355 104.625 66.515 104.975 ;
        RECT 67.035 104.625 69.195 104.975 ;
        RECT 74.035 104.625 76.195 104.975 ;
        RECT 76.715 104.625 78.875 104.975 ;
        RECT 83.715 104.625 85.875 104.975 ;
        RECT 86.395 104.625 88.555 104.975 ;
        RECT 93.395 104.625 95.555 104.975 ;
        RECT 96.075 104.625 98.235 104.975 ;
        RECT 103.075 104.625 105.235 104.975 ;
        RECT 105.680 104.145 109.620 129.525 ;
        RECT 110.020 120.620 110.190 129.670 ;
        RECT 120.310 120.620 120.480 129.670 ;
        RECT 110.740 119.555 119.760 119.725 ;
        RECT 110.020 109.840 110.190 118.890 ;
        RECT 120.310 109.840 120.480 118.890 ;
        RECT 110.740 108.775 119.760 108.945 ;
        RECT 20.120 85.515 109.620 104.145 ;
        RECT 110.020 99.060 110.190 108.110 ;
        RECT 120.310 99.060 120.480 108.110 ;
        RECT 110.740 97.995 119.760 98.165 ;
        RECT 110.020 88.280 110.190 97.330 ;
        RECT 120.310 88.280 120.480 97.330 ;
        RECT 110.740 87.215 119.760 87.385 ;
        RECT 20.120 80.065 35.870 85.515 ;
        RECT 36.190 84.835 41.000 85.195 ;
        RECT 36.190 80.745 36.550 84.835 ;
        RECT 36.860 81.055 40.330 84.525 ;
        RECT 40.640 80.745 41.000 84.835 ;
        RECT 36.190 80.385 41.000 80.745 ;
        RECT 41.320 80.065 42.310 85.515 ;
        RECT 42.630 84.835 47.440 85.195 ;
        RECT 42.630 80.745 42.990 84.835 ;
        RECT 43.300 81.055 46.770 84.525 ;
        RECT 47.080 80.745 47.440 84.835 ;
        RECT 42.630 80.385 47.440 80.745 ;
        RECT 47.760 80.065 48.750 85.515 ;
        RECT 49.070 84.835 53.880 85.195 ;
        RECT 49.070 80.745 49.430 84.835 ;
        RECT 49.740 81.055 53.210 84.525 ;
        RECT 53.520 80.745 53.880 84.835 ;
        RECT 49.070 80.385 53.880 80.745 ;
        RECT 54.200 80.065 55.190 85.515 ;
        RECT 55.510 84.835 60.320 85.195 ;
        RECT 55.510 80.745 55.870 84.835 ;
        RECT 56.180 81.055 59.650 84.525 ;
        RECT 59.960 80.745 60.320 84.835 ;
        RECT 55.510 80.385 60.320 80.745 ;
        RECT 60.640 80.065 61.630 85.515 ;
        RECT 61.950 84.835 66.760 85.195 ;
        RECT 61.950 80.745 62.310 84.835 ;
        RECT 62.620 81.055 66.090 84.525 ;
        RECT 66.400 80.745 66.760 84.835 ;
        RECT 61.950 80.385 66.760 80.745 ;
        RECT 67.080 80.065 68.070 85.515 ;
        RECT 68.390 84.835 73.200 85.195 ;
        RECT 68.390 80.745 68.750 84.835 ;
        RECT 69.060 81.055 72.530 84.525 ;
        RECT 72.840 80.745 73.200 84.835 ;
        RECT 68.390 80.385 73.200 80.745 ;
        RECT 73.520 80.065 74.510 85.515 ;
        RECT 74.830 84.835 79.640 85.195 ;
        RECT 74.830 80.745 75.190 84.835 ;
        RECT 75.500 81.055 78.970 84.525 ;
        RECT 79.280 80.745 79.640 84.835 ;
        RECT 74.830 80.385 79.640 80.745 ;
        RECT 79.960 80.065 80.950 85.515 ;
        RECT 81.270 84.835 86.080 85.195 ;
        RECT 81.270 80.745 81.630 84.835 ;
        RECT 81.940 81.055 85.410 84.525 ;
        RECT 85.720 80.745 86.080 84.835 ;
        RECT 81.270 80.385 86.080 80.745 ;
        RECT 86.400 80.065 87.390 85.515 ;
        RECT 87.710 84.835 92.520 85.195 ;
        RECT 87.710 80.745 88.070 84.835 ;
        RECT 88.380 81.055 91.850 84.525 ;
        RECT 92.160 80.745 92.520 84.835 ;
        RECT 87.710 80.385 92.520 80.745 ;
        RECT 92.840 80.065 93.830 85.515 ;
        RECT 94.150 84.835 98.960 85.195 ;
        RECT 94.150 80.745 94.510 84.835 ;
        RECT 94.820 81.055 98.290 84.525 ;
        RECT 98.600 80.745 98.960 84.835 ;
        RECT 94.150 80.385 98.960 80.745 ;
        RECT 99.280 80.065 100.270 85.515 ;
        RECT 100.590 84.835 105.400 85.195 ;
        RECT 100.590 80.745 100.950 84.835 ;
        RECT 101.260 81.055 104.730 84.525 ;
        RECT 105.040 80.745 105.400 84.835 ;
        RECT 100.590 80.385 105.400 80.745 ;
        RECT 105.720 80.065 109.620 85.515 ;
        RECT 20.120 79.075 109.620 80.065 ;
        RECT 20.120 73.625 35.870 79.075 ;
        RECT 37.130 78.755 40.360 78.770 ;
        RECT 36.190 78.395 41.000 78.755 ;
        RECT 36.190 74.305 36.550 78.395 ;
        RECT 36.860 74.615 40.330 78.085 ;
        RECT 40.640 74.305 41.000 78.395 ;
        RECT 36.190 73.945 41.000 74.305 ;
        RECT 41.320 73.625 42.310 79.075 ;
        RECT 47.760 78.785 48.750 79.075 ;
        RECT 42.630 78.395 48.750 78.785 ;
        RECT 42.630 74.305 42.990 78.395 ;
        RECT 43.300 74.615 46.770 78.085 ;
        RECT 47.080 74.305 47.440 78.395 ;
        RECT 42.630 73.945 47.440 74.305 ;
        RECT 47.760 73.625 48.750 78.395 ;
        RECT 49.070 78.395 53.880 78.785 ;
        RECT 49.070 74.305 49.430 78.395 ;
        RECT 49.740 74.615 53.210 78.085 ;
        RECT 53.520 74.305 53.880 78.395 ;
        RECT 49.070 73.945 53.880 74.305 ;
        RECT 54.200 73.625 55.190 79.075 ;
        RECT 55.510 78.395 60.320 78.785 ;
        RECT 55.510 74.305 55.870 78.395 ;
        RECT 56.180 74.615 59.650 78.085 ;
        RECT 59.960 74.305 60.320 78.395 ;
        RECT 55.510 73.945 60.320 74.305 ;
        RECT 60.640 73.625 61.630 79.075 ;
        RECT 61.950 78.395 66.760 78.785 ;
        RECT 61.950 74.305 62.310 78.395 ;
        RECT 62.620 74.615 66.090 78.085 ;
        RECT 66.400 74.305 66.760 78.395 ;
        RECT 61.950 73.945 66.760 74.305 ;
        RECT 67.080 73.625 68.070 79.075 ;
        RECT 68.390 78.395 73.200 78.785 ;
        RECT 68.390 74.305 68.750 78.395 ;
        RECT 69.060 74.615 72.530 78.085 ;
        RECT 72.840 74.305 73.200 78.395 ;
        RECT 68.390 73.945 73.200 74.305 ;
        RECT 73.520 73.625 74.510 79.075 ;
        RECT 74.830 78.395 79.640 78.785 ;
        RECT 74.830 74.305 75.190 78.395 ;
        RECT 75.500 74.615 78.970 78.085 ;
        RECT 79.280 74.305 79.640 78.395 ;
        RECT 74.830 73.945 79.640 74.305 ;
        RECT 79.960 73.625 80.950 79.075 ;
        RECT 81.270 78.395 86.080 78.780 ;
        RECT 81.270 74.305 81.630 78.395 ;
        RECT 81.940 74.615 85.410 78.085 ;
        RECT 85.720 74.305 86.080 78.395 ;
        RECT 81.270 73.945 86.080 74.305 ;
        RECT 86.400 73.625 87.390 79.075 ;
        RECT 87.710 78.395 92.520 78.780 ;
        RECT 87.710 74.305 88.070 78.395 ;
        RECT 88.380 74.615 91.850 78.085 ;
        RECT 92.160 74.305 92.520 78.395 ;
        RECT 87.710 73.945 92.520 74.305 ;
        RECT 92.840 73.625 93.830 79.075 ;
        RECT 94.150 78.395 98.960 78.780 ;
        RECT 94.150 74.305 94.510 78.395 ;
        RECT 94.820 74.615 98.290 78.085 ;
        RECT 98.600 74.305 98.960 78.395 ;
        RECT 94.150 73.945 98.960 74.305 ;
        RECT 99.280 73.625 100.270 79.075 ;
        RECT 100.590 78.395 105.400 78.755 ;
        RECT 100.590 74.305 100.950 78.395 ;
        RECT 101.260 74.615 104.730 78.085 ;
        RECT 105.040 74.305 105.400 78.395 ;
        RECT 100.590 73.945 105.400 74.305 ;
        RECT 105.720 73.625 109.620 79.075 ;
        RECT 110.020 77.500 110.190 86.550 ;
        RECT 120.310 77.500 120.480 86.550 ;
        RECT 110.740 76.435 119.760 76.605 ;
        RECT 20.120 72.635 109.620 73.625 ;
        RECT 20.120 67.185 35.870 72.635 ;
        RECT 36.190 71.955 41.000 72.315 ;
        RECT 36.190 67.865 36.550 71.955 ;
        RECT 36.860 68.175 40.330 71.645 ;
        RECT 40.640 67.865 41.000 71.955 ;
        RECT 36.190 67.505 41.000 67.865 ;
        RECT 41.320 67.185 42.310 72.635 ;
        RECT 42.630 71.955 47.440 72.315 ;
        RECT 42.630 67.865 42.990 71.955 ;
        RECT 43.300 68.175 46.770 71.645 ;
        RECT 47.080 67.865 47.440 71.955 ;
        RECT 42.630 67.505 47.440 67.865 ;
        RECT 47.760 67.185 48.750 72.635 ;
        RECT 49.070 71.955 53.880 72.315 ;
        RECT 49.070 67.865 49.430 71.955 ;
        RECT 49.740 68.175 53.210 71.645 ;
        RECT 53.520 67.865 53.880 71.955 ;
        RECT 49.070 67.505 53.880 67.865 ;
        RECT 54.200 67.185 55.190 72.635 ;
        RECT 55.510 71.955 60.320 72.315 ;
        RECT 55.510 67.865 55.870 71.955 ;
        RECT 56.180 68.175 59.650 71.645 ;
        RECT 59.960 67.865 60.320 71.955 ;
        RECT 55.510 67.505 60.320 67.865 ;
        RECT 60.640 67.185 61.630 72.635 ;
        RECT 61.950 71.955 66.760 72.315 ;
        RECT 61.950 67.865 62.310 71.955 ;
        RECT 62.620 68.175 66.090 71.645 ;
        RECT 66.400 67.865 66.760 71.955 ;
        RECT 61.950 67.505 66.760 67.865 ;
        RECT 67.080 67.185 68.070 72.635 ;
        RECT 68.390 71.955 73.200 72.315 ;
        RECT 68.390 67.865 68.750 71.955 ;
        RECT 69.060 68.175 72.530 71.645 ;
        RECT 72.840 67.865 73.200 71.955 ;
        RECT 68.390 67.505 73.200 67.865 ;
        RECT 73.520 67.185 74.510 72.635 ;
        RECT 74.830 71.955 79.640 72.315 ;
        RECT 74.830 67.865 75.190 71.955 ;
        RECT 75.500 68.175 78.970 71.645 ;
        RECT 79.280 67.865 79.640 71.955 ;
        RECT 74.830 67.505 79.640 67.865 ;
        RECT 79.960 67.185 80.950 72.635 ;
        RECT 81.270 71.955 86.080 72.315 ;
        RECT 81.270 67.865 81.630 71.955 ;
        RECT 81.940 68.175 85.410 71.645 ;
        RECT 85.720 67.865 86.080 71.955 ;
        RECT 81.270 67.505 86.080 67.865 ;
        RECT 86.400 67.185 87.390 72.635 ;
        RECT 87.710 71.955 92.520 72.315 ;
        RECT 87.710 67.865 88.070 71.955 ;
        RECT 88.380 68.175 91.850 71.645 ;
        RECT 92.160 67.865 92.520 71.955 ;
        RECT 87.710 67.505 92.520 67.865 ;
        RECT 92.840 67.185 93.830 72.635 ;
        RECT 94.150 71.955 98.960 72.315 ;
        RECT 94.150 67.865 94.510 71.955 ;
        RECT 94.820 68.175 98.290 71.645 ;
        RECT 98.600 67.865 98.960 71.955 ;
        RECT 94.150 67.505 98.960 67.865 ;
        RECT 99.280 67.185 100.270 72.635 ;
        RECT 100.590 71.955 105.400 72.315 ;
        RECT 100.590 67.865 100.950 71.955 ;
        RECT 101.260 68.175 104.730 71.645 ;
        RECT 105.040 67.865 105.400 71.955 ;
        RECT 100.590 67.505 105.400 67.865 ;
        RECT 105.720 67.185 109.620 72.635 ;
        RECT 20.120 66.195 109.620 67.185 ;
        RECT 110.020 66.720 110.190 75.770 ;
        RECT 120.310 66.720 120.480 75.770 ;
        RECT 18.445 60.985 19.395 61.155 ;
        RECT 20.120 60.745 35.870 66.195 ;
        RECT 36.190 65.515 41.000 65.875 ;
        RECT 36.190 61.425 36.550 65.515 ;
        RECT 36.860 61.735 40.330 65.205 ;
        RECT 40.640 61.425 41.000 65.515 ;
        RECT 36.190 61.065 41.000 61.425 ;
        RECT 41.320 60.745 42.310 66.195 ;
        RECT 42.630 65.515 47.440 65.875 ;
        RECT 42.630 61.425 42.990 65.515 ;
        RECT 43.300 61.735 46.770 65.205 ;
        RECT 47.080 61.425 47.440 65.515 ;
        RECT 42.630 61.065 47.440 61.425 ;
        RECT 47.760 60.745 48.750 66.195 ;
        RECT 49.070 65.515 53.880 65.875 ;
        RECT 49.070 61.425 49.430 65.515 ;
        RECT 49.740 61.735 53.210 65.205 ;
        RECT 53.520 61.425 53.880 65.515 ;
        RECT 49.070 61.065 53.880 61.425 ;
        RECT 54.200 60.745 55.190 66.195 ;
        RECT 55.510 65.515 60.320 65.875 ;
        RECT 55.510 61.425 55.870 65.515 ;
        RECT 56.180 61.735 59.650 65.205 ;
        RECT 59.960 61.425 60.320 65.515 ;
        RECT 55.510 61.065 60.320 61.425 ;
        RECT 60.640 60.745 61.630 66.195 ;
        RECT 61.950 65.515 66.760 65.875 ;
        RECT 61.950 61.425 62.310 65.515 ;
        RECT 62.620 61.735 66.090 65.205 ;
        RECT 66.400 61.425 66.760 65.515 ;
        RECT 61.950 61.065 66.760 61.425 ;
        RECT 67.080 60.745 68.070 66.195 ;
        RECT 68.390 65.515 73.200 65.875 ;
        RECT 68.390 61.425 68.750 65.515 ;
        RECT 69.060 61.735 72.530 65.205 ;
        RECT 72.840 61.425 73.200 65.515 ;
        RECT 68.390 61.065 73.200 61.425 ;
        RECT 73.520 60.745 74.510 66.195 ;
        RECT 74.830 65.515 79.640 65.875 ;
        RECT 74.830 61.425 75.190 65.515 ;
        RECT 75.500 61.735 78.970 65.205 ;
        RECT 79.280 61.425 79.640 65.515 ;
        RECT 74.830 61.065 79.640 61.425 ;
        RECT 79.960 60.745 80.950 66.195 ;
        RECT 81.270 65.515 86.080 65.875 ;
        RECT 81.270 61.425 81.630 65.515 ;
        RECT 81.940 61.735 85.410 65.205 ;
        RECT 85.720 61.425 86.080 65.515 ;
        RECT 81.270 61.065 86.080 61.425 ;
        RECT 86.400 60.745 87.390 66.195 ;
        RECT 87.710 65.515 92.520 65.875 ;
        RECT 87.710 61.425 88.070 65.515 ;
        RECT 88.380 61.735 91.850 65.205 ;
        RECT 92.160 61.425 92.520 65.515 ;
        RECT 87.710 61.065 92.520 61.425 ;
        RECT 92.840 60.745 93.830 66.195 ;
        RECT 94.150 65.515 98.960 65.875 ;
        RECT 94.150 61.425 94.510 65.515 ;
        RECT 94.820 61.735 98.290 65.205 ;
        RECT 98.600 61.425 98.960 65.515 ;
        RECT 94.150 61.065 98.960 61.425 ;
        RECT 99.280 60.745 100.270 66.195 ;
        RECT 100.590 65.515 105.400 65.875 ;
        RECT 100.590 61.425 100.950 65.515 ;
        RECT 101.260 61.735 104.730 65.205 ;
        RECT 105.040 61.425 105.400 65.515 ;
        RECT 100.590 61.065 105.400 61.425 ;
        RECT 105.720 65.855 109.620 66.195 ;
        RECT 120.880 65.855 134.130 173.205 ;
        RECT 105.720 60.745 134.130 65.855 ;
        RECT 20.120 60.595 134.130 60.745 ;
        RECT 17.680 54.910 134.130 60.595 ;
      LAYER met1 ;
        RECT 127.550 191.825 128.040 192.545 ;
        RECT 19.695 191.595 128.040 191.825 ;
        RECT 29.405 186.890 29.635 191.055 ;
        RECT 40.230 186.890 40.460 191.055 ;
        RECT 51.055 186.890 51.285 191.055 ;
        RECT 61.880 186.890 62.110 191.055 ;
        RECT 72.705 186.890 72.935 191.055 ;
        RECT 83.530 186.890 83.760 191.055 ;
        RECT 94.355 186.890 94.585 191.055 ;
        RECT 105.180 186.890 105.410 191.055 ;
        RECT 116.005 186.890 116.235 191.055 ;
        RECT 126.830 186.890 127.290 191.055 ;
        RECT 29.405 186.660 127.290 186.890 ;
        RECT 29.405 182.075 29.635 186.660 ;
        RECT 40.230 182.075 40.460 186.660 ;
        RECT 51.055 182.075 51.285 186.660 ;
        RECT 61.880 182.075 62.110 186.660 ;
        RECT 72.705 182.075 72.935 186.660 ;
        RECT 83.530 182.075 83.760 186.660 ;
        RECT 94.355 182.075 94.585 186.660 ;
        RECT 105.180 182.075 105.410 186.660 ;
        RECT 116.005 182.075 116.235 186.660 ;
        RECT 126.830 182.075 127.290 186.660 ;
        RECT 127.550 181.535 128.040 191.595 ;
        RECT 19.695 181.305 128.040 181.535 ;
        RECT 127.550 180.990 128.040 181.305 ;
        RECT 17.680 175.350 134.130 180.155 ;
        RECT 17.860 174.470 31.750 174.810 ;
        RECT 41.385 174.470 105.955 174.800 ;
        RECT 109.450 174.470 121.050 174.820 ;
        RECT 18.400 170.275 18.630 174.470 ;
        RECT 24.690 170.580 24.920 173.885 ;
        RECT 24.640 170.255 24.980 170.580 ;
        RECT 30.980 170.275 31.210 174.470 ;
        RECT 36.270 169.875 36.730 170.105 ;
        RECT 18.970 169.645 36.730 169.875 ;
        RECT 18.730 161.475 19.060 169.195 ;
        RECT 24.695 164.465 24.925 169.645 ;
        RECT 26.320 168.705 26.950 169.195 ;
        RECT 25.115 168.475 27.795 168.705 ;
        RECT 41.385 168.320 41.735 174.270 ;
        RECT 42.105 169.255 42.335 174.470 ;
        RECT 45.020 173.495 45.305 174.470 ;
        RECT 42.675 173.265 48.055 173.495 ;
        RECT 48.395 169.255 48.625 174.470 ;
        RECT 51.330 173.495 51.615 174.470 ;
        RECT 48.965 173.265 54.345 173.495 ;
        RECT 54.685 169.255 54.915 174.470 ;
        RECT 55.255 173.265 60.635 173.620 ;
        RECT 61.545 173.265 66.925 173.620 ;
        RECT 27.985 166.415 28.215 168.075 ;
        RECT 27.985 166.185 30.520 166.415 ;
        RECT 27.985 164.465 28.215 166.185 ;
        RECT 18.465 161.245 19.810 161.475 ;
        RECT 19.580 66.225 19.810 161.245 ;
        RECT 30.290 143.865 30.520 166.185 ;
        RECT 60.975 166.085 61.205 172.865 ;
        RECT 67.265 169.255 67.495 174.470 ;
        RECT 67.835 173.265 73.215 173.620 ;
        RECT 74.125 173.265 79.505 173.620 ;
        RECT 60.660 165.625 61.205 166.085 ;
        RECT 73.555 166.085 73.785 172.865 ;
        RECT 79.845 169.255 80.075 174.470 ;
        RECT 80.415 173.265 85.795 173.620 ;
        RECT 86.705 173.265 92.085 173.620 ;
        RECT 86.135 167.605 86.365 172.865 ;
        RECT 92.425 169.255 92.655 174.470 ;
        RECT 95.225 173.495 95.510 174.470 ;
        RECT 92.995 173.265 98.375 173.495 ;
        RECT 98.715 169.255 98.945 174.470 ;
        RECT 101.690 173.495 101.975 174.470 ;
        RECT 99.285 173.265 104.665 173.495 ;
        RECT 105.005 169.255 105.235 174.470 ;
        RECT 114.830 173.655 115.060 174.470 ;
        RECT 110.760 173.425 119.740 173.655 ;
        RECT 86.135 167.050 86.730 167.605 ;
        RECT 73.555 165.625 74.100 166.085 ;
        RECT 38.590 155.570 107.035 156.475 ;
        RECT 55.710 151.375 55.940 155.570 ;
        RECT 56.280 150.550 61.660 150.975 ;
        RECT 36.275 150.150 36.720 150.385 ;
        RECT 62.000 150.150 62.230 154.985 ;
        RECT 68.290 151.375 68.520 155.570 ;
        RECT 74.580 152.880 74.810 154.985 ;
        RECT 71.375 152.650 78.060 152.880 ;
        RECT 71.375 150.975 71.605 152.650 ;
        RECT 62.570 150.550 67.950 150.975 ;
        RECT 68.860 150.550 74.240 150.975 ;
        RECT 74.580 150.150 74.810 152.650 ;
        RECT 77.830 150.975 78.060 152.650 ;
        RECT 80.870 151.375 81.100 155.570 ;
        RECT 75.150 150.550 80.530 150.975 ;
        RECT 36.270 149.920 67.910 150.150 ;
        RECT 30.165 143.400 30.625 143.865 ;
        RECT 61.160 139.055 61.390 149.145 ;
        RECT 67.450 145.535 67.910 149.920 ;
        RECT 68.900 149.920 74.810 150.150 ;
        RECT 68.900 145.535 69.350 149.920 ;
        RECT 61.730 144.865 68.495 145.180 ;
        RECT 69.690 144.865 75.070 145.180 ;
        RECT 68.250 143.715 68.495 144.865 ;
        RECT 61.730 143.400 67.185 143.715 ;
        RECT 68.250 143.400 75.070 143.715 ;
        RECT 67.450 139.435 67.770 143.045 ;
        RECT 69.030 139.435 69.350 143.045 ;
        RECT 75.410 139.055 75.640 149.145 ;
        RECT 61.160 138.845 75.640 139.055 ;
        RECT 57.930 137.610 66.910 138.035 ;
        RECT 68.250 137.430 68.660 138.845 ;
        RECT 69.890 137.610 78.870 138.035 ;
        RECT 57.160 136.560 57.390 137.430 ;
        RECT 67.450 136.970 69.350 137.430 ;
        RECT 79.410 136.560 79.640 137.430 ;
        RECT 38.585 135.655 107.030 136.560 ;
        RECT 38.590 135.595 39.190 135.655 ;
        RECT 106.430 135.605 107.030 135.655 ;
        RECT 37.230 129.525 107.030 129.840 ;
        RECT 37.230 129.045 37.520 129.525 ;
        RECT 38.915 129.045 39.205 129.525 ;
        RECT 37.230 128.695 40.155 129.045 ;
        RECT 45.910 128.995 46.245 129.525 ;
        RECT 48.590 128.995 48.880 129.525 ;
        RECT 55.575 128.995 55.865 129.525 ;
        RECT 58.285 128.995 58.575 129.525 ;
        RECT 65.310 128.995 65.600 129.525 ;
        RECT 67.935 128.995 68.225 129.525 ;
        RECT 74.940 128.995 75.230 129.525 ;
        RECT 77.630 128.995 77.920 129.525 ;
        RECT 84.655 128.995 84.945 129.525 ;
        RECT 87.365 128.995 87.655 129.525 ;
        RECT 94.320 128.995 94.610 129.525 ;
        RECT 97.035 128.995 97.325 129.525 ;
        RECT 104.035 129.045 104.325 129.525 ;
        RECT 105.680 129.045 105.970 129.525 ;
        RECT 45.020 128.745 47.125 128.995 ;
        RECT 47.705 128.745 49.810 128.995 ;
        RECT 54.700 128.745 56.805 128.995 ;
        RECT 57.385 128.745 59.490 128.995 ;
        RECT 64.380 128.745 66.485 128.995 ;
        RECT 67.065 128.745 69.170 128.995 ;
        RECT 74.060 128.745 76.165 128.995 ;
        RECT 76.745 128.745 78.850 128.995 ;
        RECT 83.740 128.745 85.845 128.995 ;
        RECT 86.425 128.745 88.530 128.995 ;
        RECT 93.420 128.745 95.525 128.995 ;
        RECT 96.105 128.745 98.210 128.995 ;
        RECT 37.230 128.215 37.520 128.695 ;
        RECT 38.915 128.215 39.205 128.695 ;
        RECT 37.230 127.865 40.155 128.215 ;
        RECT 45.910 128.165 46.245 128.745 ;
        RECT 48.590 128.165 48.880 128.745 ;
        RECT 55.575 128.165 55.865 128.745 ;
        RECT 58.285 128.165 58.575 128.745 ;
        RECT 65.310 128.165 65.600 128.745 ;
        RECT 67.935 128.165 68.225 128.745 ;
        RECT 74.940 128.165 75.230 128.745 ;
        RECT 77.630 128.165 77.920 128.745 ;
        RECT 84.655 128.165 84.945 128.745 ;
        RECT 87.365 128.165 87.655 128.745 ;
        RECT 94.320 128.165 94.610 128.745 ;
        RECT 97.035 128.165 97.325 128.745 ;
        RECT 103.075 128.695 105.970 129.045 ;
        RECT 104.035 128.215 104.325 128.695 ;
        RECT 105.680 128.215 105.970 128.695 ;
        RECT 45.020 127.915 47.125 128.165 ;
        RECT 47.705 127.915 49.810 128.165 ;
        RECT 54.700 127.915 56.805 128.165 ;
        RECT 57.385 127.915 59.490 128.165 ;
        RECT 64.380 127.915 66.485 128.165 ;
        RECT 67.065 127.915 69.170 128.165 ;
        RECT 74.060 127.915 76.165 128.165 ;
        RECT 76.745 127.915 78.850 128.165 ;
        RECT 83.740 127.915 85.845 128.165 ;
        RECT 86.425 127.915 88.530 128.165 ;
        RECT 93.420 127.915 95.525 128.165 ;
        RECT 96.105 127.915 98.210 128.165 ;
        RECT 37.230 127.385 37.520 127.865 ;
        RECT 38.915 127.385 39.205 127.865 ;
        RECT 37.230 127.035 40.155 127.385 ;
        RECT 45.910 127.335 46.245 127.915 ;
        RECT 55.575 127.865 55.865 127.915 ;
        RECT 58.285 127.865 58.575 127.915 ;
        RECT 65.310 127.865 65.600 127.915 ;
        RECT 67.935 127.865 68.225 127.915 ;
        RECT 74.940 127.870 75.230 127.915 ;
        RECT 77.630 127.865 77.920 127.915 ;
        RECT 84.655 127.865 84.945 127.915 ;
        RECT 87.365 127.865 87.655 127.915 ;
        RECT 94.320 127.865 94.610 127.915 ;
        RECT 45.020 127.085 47.125 127.335 ;
        RECT 47.705 127.085 49.810 127.705 ;
        RECT 37.230 126.555 37.520 127.035 ;
        RECT 38.915 126.555 39.205 127.035 ;
        RECT 37.230 126.205 40.155 126.555 ;
        RECT 45.910 126.505 46.245 127.085 ;
        RECT 45.020 126.255 47.125 126.505 ;
        RECT 37.230 125.725 37.520 126.205 ;
        RECT 38.915 125.725 39.205 126.205 ;
        RECT 37.230 125.375 40.155 125.725 ;
        RECT 45.910 125.675 46.245 126.255 ;
        RECT 45.020 125.425 47.125 125.675 ;
        RECT 37.230 124.895 37.520 125.375 ;
        RECT 38.915 124.895 39.205 125.375 ;
        RECT 37.230 124.545 40.155 124.895 ;
        RECT 45.910 124.845 46.245 125.425 ;
        RECT 47.705 125.420 49.810 126.505 ;
        RECT 54.700 126.255 56.805 127.335 ;
        RECT 57.385 127.085 59.490 127.705 ;
        RECT 97.035 127.335 97.325 127.915 ;
        RECT 103.075 127.865 105.970 128.215 ;
        RECT 104.035 127.385 104.325 127.865 ;
        RECT 105.680 127.385 105.970 127.865 ;
        RECT 64.380 127.085 69.170 127.335 ;
        RECT 74.060 127.085 78.850 127.335 ;
        RECT 83.740 127.085 88.530 127.335 ;
        RECT 66.115 126.505 67.175 126.510 ;
        RECT 75.825 126.505 76.885 126.510 ;
        RECT 55.635 126.250 55.860 126.255 ;
        RECT 45.020 124.595 47.125 124.845 ;
        RECT 37.230 124.065 37.520 124.545 ;
        RECT 38.915 124.065 39.205 124.545 ;
        RECT 37.230 123.715 40.155 124.065 ;
        RECT 45.910 124.015 46.245 124.595 ;
        RECT 45.020 123.765 47.125 124.015 ;
        RECT 47.705 123.765 49.810 124.845 ;
        RECT 54.700 124.595 56.805 125.675 ;
        RECT 57.385 125.425 59.490 126.505 ;
        RECT 64.380 126.255 69.170 126.505 ;
        RECT 74.060 126.255 78.850 126.505 ;
        RECT 83.740 126.255 88.530 126.505 ;
        RECT 93.420 126.255 95.525 127.335 ;
        RECT 96.105 127.085 98.210 127.335 ;
        RECT 97.035 126.505 97.325 127.085 ;
        RECT 103.075 127.035 105.970 127.385 ;
        RECT 104.035 126.555 104.325 127.035 ;
        RECT 105.680 126.555 105.970 127.035 ;
        RECT 96.105 126.255 98.210 126.505 ;
        RECT 85.535 126.250 86.595 126.255 ;
        RECT 97.035 125.675 97.325 126.255 ;
        RECT 103.075 126.205 105.970 126.555 ;
        RECT 104.035 125.725 104.325 126.205 ;
        RECT 105.680 125.725 105.970 126.205 ;
        RECT 64.380 125.425 69.170 125.675 ;
        RECT 74.060 125.425 78.850 125.675 ;
        RECT 83.740 125.425 88.530 125.675 ;
        RECT 75.895 124.845 76.965 124.850 ;
        RECT 54.695 123.765 56.805 124.015 ;
        RECT 57.385 123.765 59.490 124.845 ;
        RECT 64.380 124.595 69.170 124.845 ;
        RECT 74.060 124.595 78.850 124.845 ;
        RECT 83.740 124.595 88.530 124.845 ;
        RECT 93.415 124.595 95.525 125.675 ;
        RECT 96.105 125.425 98.210 125.675 ;
        RECT 97.035 124.845 97.325 125.425 ;
        RECT 103.075 125.375 105.970 125.725 ;
        RECT 104.035 124.895 104.325 125.375 ;
        RECT 105.680 124.895 105.970 125.375 ;
        RECT 96.105 124.595 98.210 124.845 ;
        RECT 66.240 124.590 67.310 124.595 ;
        RECT 85.560 124.590 86.630 124.595 ;
        RECT 66.440 124.015 67.110 124.020 ;
        RECT 76.120 124.015 76.790 124.020 ;
        RECT 85.810 124.015 86.480 124.020 ;
        RECT 97.035 124.015 97.325 124.595 ;
        RECT 103.075 124.545 105.970 124.895 ;
        RECT 104.035 124.065 104.325 124.545 ;
        RECT 105.680 124.065 105.970 124.545 ;
        RECT 64.380 123.765 69.170 124.015 ;
        RECT 74.060 123.765 78.850 124.015 ;
        RECT 83.740 123.765 88.530 124.015 ;
        RECT 37.230 123.235 37.520 123.715 ;
        RECT 38.915 123.235 39.205 123.715 ;
        RECT 37.230 122.885 40.155 123.235 ;
        RECT 45.910 123.185 46.245 123.765 ;
        RECT 54.695 123.185 56.800 123.765 ;
        RECT 75.960 123.185 76.910 123.190 ;
        RECT 85.620 123.185 86.570 123.190 ;
        RECT 45.020 122.935 47.125 123.185 ;
        RECT 37.230 122.405 37.520 122.885 ;
        RECT 38.915 122.405 39.205 122.885 ;
        RECT 37.230 122.055 40.155 122.405 ;
        RECT 45.910 122.355 46.245 122.935 ;
        RECT 45.020 122.105 47.125 122.355 ;
        RECT 47.705 122.105 49.810 123.185 ;
        RECT 54.695 122.935 56.805 123.185 ;
        RECT 37.230 121.575 37.520 122.055 ;
        RECT 38.915 121.575 39.205 122.055 ;
        RECT 37.230 121.225 40.155 121.575 ;
        RECT 45.910 121.525 46.245 122.105 ;
        RECT 45.020 121.275 47.125 121.525 ;
        RECT 37.230 120.745 37.520 121.225 ;
        RECT 38.915 120.745 39.205 121.225 ;
        RECT 37.230 120.395 40.155 120.745 ;
        RECT 45.910 120.695 46.245 121.275 ;
        RECT 45.020 120.445 47.125 120.695 ;
        RECT 37.230 119.915 37.520 120.395 ;
        RECT 38.915 119.915 39.205 120.395 ;
        RECT 37.230 119.565 40.155 119.915 ;
        RECT 45.910 119.865 46.245 120.445 ;
        RECT 47.705 120.440 49.810 121.525 ;
        RECT 54.700 121.275 56.805 122.355 ;
        RECT 57.380 122.100 59.490 123.185 ;
        RECT 64.380 122.935 69.170 123.185 ;
        RECT 74.060 122.935 78.850 123.185 ;
        RECT 83.740 122.935 88.530 123.185 ;
        RECT 66.215 122.930 67.165 122.935 ;
        RECT 93.420 122.930 95.530 124.015 ;
        RECT 96.105 123.765 98.210 124.015 ;
        RECT 97.035 123.185 97.325 123.765 ;
        RECT 103.075 123.715 105.970 124.065 ;
        RECT 104.035 123.235 104.325 123.715 ;
        RECT 105.680 123.235 105.970 123.715 ;
        RECT 96.105 122.935 98.210 123.185 ;
        RECT 66.275 122.355 67.330 122.360 ;
        RECT 97.035 122.355 97.325 122.935 ;
        RECT 103.075 122.885 105.970 123.235 ;
        RECT 104.035 122.405 104.325 122.885 ;
        RECT 105.680 122.405 105.970 122.885 ;
        RECT 64.380 122.105 69.170 122.355 ;
        RECT 74.060 122.105 78.850 122.355 ;
        RECT 83.740 122.105 88.530 122.355 ;
        RECT 93.420 122.350 95.525 122.355 ;
        RECT 76.105 122.100 77.160 122.105 ;
        RECT 85.675 122.100 86.730 122.105 ;
        RECT 66.390 121.525 67.180 121.530 ;
        RECT 45.020 119.615 47.125 119.865 ;
        RECT 47.705 119.615 49.810 120.235 ;
        RECT 54.700 119.615 56.805 120.695 ;
        RECT 57.385 120.445 59.490 121.525 ;
        RECT 64.380 121.275 69.170 121.525 ;
        RECT 74.060 121.275 78.850 121.525 ;
        RECT 83.740 121.275 88.530 121.525 ;
        RECT 93.420 121.295 95.530 122.350 ;
        RECT 96.105 122.105 98.210 122.355 ;
        RECT 97.035 121.525 97.325 122.105 ;
        RECT 103.075 122.055 105.970 122.405 ;
        RECT 104.035 121.575 104.325 122.055 ;
        RECT 105.680 121.575 105.970 122.055 ;
        RECT 93.420 121.275 95.525 121.295 ;
        RECT 96.105 121.275 98.210 121.525 ;
        RECT 76.010 121.270 76.800 121.275 ;
        RECT 97.035 120.695 97.325 121.275 ;
        RECT 103.075 121.225 105.970 121.575 ;
        RECT 104.035 120.745 104.325 121.225 ;
        RECT 105.680 120.745 105.970 121.225 ;
        RECT 64.380 120.445 69.170 120.695 ;
        RECT 74.060 120.445 78.850 120.695 ;
        RECT 83.740 120.445 88.530 120.695 ;
        RECT 66.445 119.865 67.265 119.870 ;
        RECT 37.230 119.085 37.520 119.565 ;
        RECT 38.915 119.085 39.205 119.565 ;
        RECT 37.230 118.735 40.155 119.085 ;
        RECT 45.910 119.035 46.245 119.615 ;
        RECT 45.020 118.785 47.125 119.035 ;
        RECT 37.230 118.255 37.520 118.735 ;
        RECT 38.915 118.255 39.205 118.735 ;
        RECT 37.230 117.905 40.155 118.255 ;
        RECT 45.910 118.205 46.245 118.785 ;
        RECT 47.675 118.735 49.835 119.085 ;
        RECT 54.700 118.785 56.805 119.035 ;
        RECT 57.385 118.785 59.495 119.865 ;
        RECT 64.380 119.615 69.170 119.865 ;
        RECT 74.060 119.615 78.850 119.865 ;
        RECT 83.740 119.615 88.530 119.865 ;
        RECT 93.420 119.615 95.525 120.695 ;
        RECT 96.105 120.445 98.210 120.695 ;
        RECT 97.035 119.865 97.325 120.445 ;
        RECT 103.075 120.395 105.970 120.745 ;
        RECT 104.035 119.915 104.325 120.395 ;
        RECT 105.680 119.915 105.970 120.395 ;
        RECT 96.105 119.615 98.210 119.865 ;
        RECT 76.150 119.610 76.970 119.615 ;
        RECT 85.745 119.610 86.565 119.615 ;
        RECT 85.765 119.035 86.500 119.040 ;
        RECT 97.035 119.035 97.325 119.615 ;
        RECT 103.075 119.565 105.970 119.915 ;
        RECT 104.035 119.085 104.325 119.565 ;
        RECT 105.680 119.085 105.970 119.565 ;
        RECT 64.380 118.790 69.170 119.035 ;
        RECT 64.380 118.785 66.485 118.790 ;
        RECT 67.065 118.785 69.170 118.790 ;
        RECT 74.060 118.785 78.850 119.035 ;
        RECT 83.740 118.785 88.530 119.035 ;
        RECT 54.700 118.205 56.800 118.785 ;
        RECT 76.025 118.780 76.760 118.785 ;
        RECT 45.020 117.955 47.125 118.205 ;
        RECT 47.700 117.955 49.810 118.205 ;
        RECT 54.700 117.955 56.805 118.205 ;
        RECT 37.230 117.425 37.520 117.905 ;
        RECT 38.915 117.425 39.205 117.905 ;
        RECT 37.230 117.075 40.155 117.425 ;
        RECT 45.910 117.375 46.245 117.955 ;
        RECT 47.700 117.375 49.805 117.955 ;
        RECT 57.355 117.900 59.515 118.255 ;
        RECT 64.380 117.955 69.170 118.205 ;
        RECT 74.060 117.955 78.850 118.205 ;
        RECT 83.740 117.955 88.530 118.205 ;
        RECT 93.420 117.955 95.525 119.035 ;
        RECT 96.105 118.785 98.210 119.035 ;
        RECT 97.035 118.205 97.325 118.785 ;
        RECT 103.075 118.735 105.970 119.085 ;
        RECT 104.035 118.255 104.325 118.735 ;
        RECT 105.680 118.255 105.970 118.735 ;
        RECT 96.105 117.955 98.210 118.205 ;
        RECT 97.035 117.375 97.325 117.955 ;
        RECT 103.075 117.905 105.970 118.255 ;
        RECT 104.035 117.425 104.325 117.905 ;
        RECT 105.680 117.425 105.970 117.905 ;
        RECT 45.020 117.125 47.125 117.375 ;
        RECT 47.700 117.125 49.810 117.375 ;
        RECT 54.700 117.370 56.805 117.375 ;
        RECT 57.385 117.370 59.490 117.375 ;
        RECT 54.700 117.125 59.490 117.370 ;
        RECT 64.380 117.125 69.170 117.375 ;
        RECT 74.060 117.125 78.850 117.375 ;
        RECT 83.740 117.125 88.530 117.375 ;
        RECT 37.230 116.595 37.520 117.075 ;
        RECT 38.915 116.595 39.205 117.075 ;
        RECT 37.230 116.245 40.155 116.595 ;
        RECT 45.910 116.545 46.245 117.125 ;
        RECT 47.700 117.120 49.805 117.125 ;
        RECT 56.470 117.120 57.695 117.125 ;
        RECT 45.020 116.295 47.125 116.545 ;
        RECT 37.230 115.765 37.520 116.245 ;
        RECT 38.915 115.765 39.205 116.245 ;
        RECT 37.230 115.415 40.155 115.765 ;
        RECT 45.910 115.715 46.245 116.295 ;
        RECT 45.020 115.465 47.125 115.715 ;
        RECT 47.705 115.465 49.810 116.545 ;
        RECT 54.700 116.295 59.490 116.545 ;
        RECT 64.380 116.295 69.170 116.545 ;
        RECT 74.060 116.295 78.850 116.545 ;
        RECT 83.740 116.295 88.530 116.545 ;
        RECT 93.420 116.295 95.525 117.375 ;
        RECT 96.105 117.125 98.210 117.375 ;
        RECT 97.035 116.545 97.325 117.125 ;
        RECT 103.075 117.075 105.970 117.425 ;
        RECT 104.035 116.595 104.325 117.075 ;
        RECT 105.680 116.595 105.970 117.075 ;
        RECT 96.105 116.295 98.210 116.545 ;
        RECT 97.035 115.715 97.325 116.295 ;
        RECT 103.075 116.245 105.970 116.595 ;
        RECT 104.035 115.765 104.325 116.245 ;
        RECT 105.680 115.765 105.970 116.245 ;
        RECT 54.700 115.465 59.490 115.715 ;
        RECT 64.380 115.465 69.170 115.715 ;
        RECT 74.060 115.465 78.850 115.715 ;
        RECT 83.740 115.465 88.530 115.715 ;
        RECT 93.420 115.710 95.525 115.715 ;
        RECT 37.230 114.935 37.520 115.415 ;
        RECT 38.915 114.935 39.205 115.415 ;
        RECT 37.230 114.585 40.155 114.935 ;
        RECT 45.910 114.885 46.245 115.465 ;
        RECT 45.020 114.635 47.125 114.885 ;
        RECT 37.230 114.105 37.520 114.585 ;
        RECT 38.915 114.105 39.205 114.585 ;
        RECT 37.230 113.755 40.155 114.105 ;
        RECT 45.910 114.055 46.245 114.635 ;
        RECT 45.020 113.805 47.125 114.055 ;
        RECT 37.230 113.275 37.520 113.755 ;
        RECT 38.915 113.275 39.205 113.755 ;
        RECT 37.230 112.925 40.155 113.275 ;
        RECT 45.910 113.225 46.245 113.805 ;
        RECT 47.705 113.800 49.810 114.885 ;
        RECT 54.700 114.635 59.490 114.885 ;
        RECT 64.380 114.635 69.170 114.885 ;
        RECT 74.060 114.635 78.850 114.885 ;
        RECT 83.740 114.635 88.530 114.885 ;
        RECT 93.415 114.635 95.530 115.710 ;
        RECT 96.105 115.465 98.210 115.715 ;
        RECT 97.035 114.885 97.325 115.465 ;
        RECT 103.075 115.415 105.970 115.765 ;
        RECT 104.035 114.935 104.325 115.415 ;
        RECT 105.680 114.935 105.970 115.415 ;
        RECT 96.105 114.635 98.210 114.885 ;
        RECT 97.035 114.055 97.325 114.635 ;
        RECT 103.075 114.585 105.970 114.935 ;
        RECT 104.035 114.105 104.325 114.585 ;
        RECT 105.680 114.105 105.970 114.585 ;
        RECT 54.700 113.805 59.490 114.055 ;
        RECT 64.380 113.805 69.170 114.055 ;
        RECT 74.060 113.805 78.850 114.055 ;
        RECT 83.740 113.805 88.530 114.055 ;
        RECT 66.355 113.225 67.180 113.230 ;
        RECT 45.020 112.975 47.125 113.225 ;
        RECT 37.230 112.445 37.520 112.925 ;
        RECT 38.915 112.445 39.205 112.925 ;
        RECT 37.230 112.095 40.155 112.445 ;
        RECT 45.910 112.395 46.245 112.975 ;
        RECT 45.020 112.145 47.125 112.395 ;
        RECT 37.230 111.615 37.520 112.095 ;
        RECT 38.915 111.615 39.205 112.095 ;
        RECT 37.230 111.265 40.155 111.615 ;
        RECT 45.910 111.565 46.245 112.145 ;
        RECT 47.705 112.140 49.810 113.225 ;
        RECT 54.700 112.975 59.490 113.225 ;
        RECT 64.380 112.980 69.170 113.225 ;
        RECT 64.380 112.975 66.485 112.980 ;
        RECT 67.065 112.975 69.170 112.980 ;
        RECT 74.060 112.975 78.850 113.225 ;
        RECT 83.740 112.975 88.530 113.225 ;
        RECT 93.420 112.970 95.525 114.055 ;
        RECT 96.105 113.805 98.210 114.055 ;
        RECT 97.035 113.225 97.325 113.805 ;
        RECT 103.075 113.755 105.970 114.105 ;
        RECT 104.035 113.275 104.325 113.755 ;
        RECT 105.680 113.275 105.970 113.755 ;
        RECT 96.105 112.975 98.210 113.225 ;
        RECT 97.035 112.395 97.325 112.975 ;
        RECT 103.075 112.925 105.970 113.275 ;
        RECT 104.035 112.445 104.325 112.925 ;
        RECT 105.680 112.445 105.970 112.925 ;
        RECT 54.700 112.145 59.490 112.395 ;
        RECT 64.380 112.145 69.170 112.395 ;
        RECT 74.060 112.145 78.850 112.395 ;
        RECT 83.740 112.145 88.530 112.395 ;
        RECT 45.020 111.315 47.125 111.565 ;
        RECT 37.230 110.785 37.520 111.265 ;
        RECT 38.915 110.785 39.205 111.265 ;
        RECT 37.230 110.435 40.155 110.785 ;
        RECT 45.910 110.735 46.245 111.315 ;
        RECT 45.020 110.485 47.125 110.735 ;
        RECT 47.705 110.485 49.810 111.565 ;
        RECT 54.700 111.315 59.490 111.565 ;
        RECT 64.380 111.315 69.170 111.565 ;
        RECT 74.060 111.315 78.850 111.565 ;
        RECT 83.740 111.315 88.530 111.565 ;
        RECT 93.420 111.315 95.525 112.395 ;
        RECT 96.105 112.145 98.210 112.395 ;
        RECT 97.035 111.565 97.325 112.145 ;
        RECT 103.075 112.095 105.970 112.445 ;
        RECT 104.035 111.615 104.325 112.095 ;
        RECT 105.680 111.615 105.970 112.095 ;
        RECT 96.105 111.315 98.210 111.565 ;
        RECT 97.035 110.735 97.325 111.315 ;
        RECT 103.075 111.265 105.970 111.615 ;
        RECT 104.035 110.785 104.325 111.265 ;
        RECT 105.680 110.785 105.970 111.265 ;
        RECT 54.700 110.485 59.490 110.735 ;
        RECT 64.380 110.485 69.170 110.735 ;
        RECT 74.060 110.485 78.850 110.735 ;
        RECT 83.740 110.485 88.530 110.735 ;
        RECT 37.230 109.955 37.520 110.435 ;
        RECT 38.915 109.955 39.205 110.435 ;
        RECT 37.230 109.605 40.155 109.955 ;
        RECT 45.910 109.905 46.245 110.485 ;
        RECT 45.020 109.655 47.125 109.905 ;
        RECT 37.230 109.125 37.520 109.605 ;
        RECT 38.915 109.125 39.205 109.605 ;
        RECT 37.230 108.775 40.155 109.125 ;
        RECT 45.910 109.075 46.245 109.655 ;
        RECT 45.020 108.825 47.125 109.075 ;
        RECT 47.705 108.825 49.810 109.905 ;
        RECT 54.700 109.655 59.490 109.905 ;
        RECT 64.380 109.655 69.170 109.905 ;
        RECT 74.060 109.655 78.850 109.905 ;
        RECT 83.740 109.655 88.530 109.905 ;
        RECT 93.420 109.655 95.525 110.735 ;
        RECT 96.105 110.485 98.210 110.735 ;
        RECT 97.035 109.905 97.325 110.485 ;
        RECT 103.075 110.435 105.970 110.785 ;
        RECT 104.035 109.955 104.325 110.435 ;
        RECT 105.680 109.955 105.970 110.435 ;
        RECT 96.105 109.655 98.210 109.905 ;
        RECT 97.035 109.075 97.325 109.655 ;
        RECT 103.075 109.605 105.970 109.955 ;
        RECT 104.035 109.125 104.325 109.605 ;
        RECT 105.680 109.125 105.970 109.605 ;
        RECT 54.700 108.825 59.490 109.075 ;
        RECT 64.380 108.825 69.170 109.075 ;
        RECT 74.060 108.825 78.850 109.075 ;
        RECT 83.740 108.825 88.530 109.075 ;
        RECT 37.230 108.295 37.520 108.775 ;
        RECT 38.915 108.295 39.205 108.775 ;
        RECT 37.230 107.945 40.155 108.295 ;
        RECT 45.910 108.245 46.245 108.825 ;
        RECT 45.020 107.995 47.125 108.245 ;
        RECT 37.230 107.465 37.520 107.945 ;
        RECT 38.915 107.465 39.205 107.945 ;
        RECT 37.230 107.115 40.155 107.465 ;
        RECT 45.910 107.415 46.245 107.995 ;
        RECT 45.020 107.165 47.125 107.415 ;
        RECT 47.705 107.165 49.810 108.245 ;
        RECT 54.700 107.995 59.490 108.245 ;
        RECT 64.380 107.995 69.170 108.245 ;
        RECT 74.060 107.995 78.850 108.245 ;
        RECT 83.740 107.995 88.530 108.245 ;
        RECT 93.420 107.995 95.530 109.075 ;
        RECT 96.105 108.825 98.210 109.075 ;
        RECT 97.035 108.245 97.325 108.825 ;
        RECT 103.075 108.775 105.970 109.125 ;
        RECT 104.035 108.295 104.325 108.775 ;
        RECT 105.680 108.295 105.970 108.775 ;
        RECT 96.105 107.995 98.210 108.245 ;
        RECT 97.035 107.415 97.325 107.995 ;
        RECT 103.075 107.945 105.970 108.295 ;
        RECT 104.035 107.465 104.325 107.945 ;
        RECT 105.680 107.465 105.970 107.945 ;
        RECT 54.700 107.165 59.490 107.415 ;
        RECT 64.380 107.165 69.170 107.415 ;
        RECT 74.060 107.165 78.850 107.415 ;
        RECT 83.740 107.165 88.530 107.415 ;
        RECT 37.230 106.635 37.520 107.115 ;
        RECT 38.915 106.635 39.205 107.115 ;
        RECT 37.230 106.285 40.155 106.635 ;
        RECT 45.910 106.585 46.245 107.165 ;
        RECT 45.020 106.335 47.125 106.585 ;
        RECT 47.705 106.335 49.810 106.585 ;
        RECT 54.700 106.335 56.805 106.585 ;
        RECT 57.385 106.335 59.490 106.585 ;
        RECT 64.380 106.335 66.585 106.585 ;
        RECT 37.230 105.810 37.520 106.285 ;
        RECT 38.915 105.810 39.205 106.285 ;
        RECT 37.230 105.460 40.155 105.810 ;
        RECT 45.910 105.755 46.245 106.335 ;
        RECT 48.635 105.755 48.925 106.335 ;
        RECT 55.610 105.755 55.900 106.335 ;
        RECT 58.315 105.755 58.605 106.335 ;
        RECT 65.245 105.755 65.535 106.335 ;
        RECT 67.035 106.285 69.195 106.640 ;
        RECT 74.060 106.335 78.850 106.585 ;
        RECT 83.740 106.335 85.865 106.585 ;
        RECT 86.425 106.335 88.530 106.955 ;
        RECT 93.420 106.335 95.525 107.415 ;
        RECT 96.105 107.165 98.210 107.415 ;
        RECT 97.035 106.585 97.325 107.165 ;
        RECT 103.075 107.115 105.970 107.465 ;
        RECT 104.035 106.635 104.325 107.115 ;
        RECT 105.680 106.635 105.970 107.115 ;
        RECT 96.105 106.335 98.210 106.585 ;
        RECT 67.970 105.755 68.260 106.285 ;
        RECT 74.930 105.755 75.220 106.335 ;
        RECT 77.655 105.755 77.945 106.335 ;
        RECT 84.665 105.755 84.955 106.335 ;
        RECT 87.335 105.755 87.625 105.805 ;
        RECT 94.300 105.755 94.590 105.805 ;
        RECT 97.035 105.755 97.325 106.335 ;
        RECT 103.075 106.285 105.970 106.635 ;
        RECT 104.035 105.805 104.325 106.285 ;
        RECT 105.680 105.805 105.970 106.285 ;
        RECT 45.020 105.505 47.125 105.755 ;
        RECT 47.705 105.505 49.810 105.755 ;
        RECT 54.700 105.505 56.805 105.755 ;
        RECT 57.385 105.505 59.490 105.755 ;
        RECT 64.380 105.505 66.485 105.755 ;
        RECT 67.065 105.505 69.170 105.755 ;
        RECT 74.060 105.505 78.850 105.755 ;
        RECT 83.740 105.505 88.530 105.755 ;
        RECT 93.420 105.505 98.210 105.755 ;
        RECT 37.230 104.975 37.520 105.460 ;
        RECT 38.915 104.975 39.205 105.460 ;
        RECT 37.230 104.625 40.155 104.975 ;
        RECT 45.910 104.925 46.245 105.505 ;
        RECT 48.635 104.925 48.925 105.505 ;
        RECT 55.610 104.925 55.900 105.505 ;
        RECT 58.315 104.925 58.605 105.505 ;
        RECT 65.245 104.925 65.535 105.505 ;
        RECT 67.970 104.925 68.260 105.505 ;
        RECT 74.930 104.925 75.220 105.505 ;
        RECT 77.655 104.925 77.945 105.505 ;
        RECT 84.665 104.925 84.955 105.505 ;
        RECT 87.335 104.925 87.625 105.505 ;
        RECT 94.300 104.925 94.590 105.505 ;
        RECT 97.035 104.925 97.325 105.505 ;
        RECT 103.075 105.455 105.970 105.805 ;
        RECT 104.035 104.975 104.325 105.455 ;
        RECT 105.680 104.975 105.970 105.455 ;
        RECT 45.020 104.675 47.125 104.925 ;
        RECT 47.705 104.675 49.810 104.925 ;
        RECT 54.700 104.675 56.805 104.925 ;
        RECT 57.385 104.675 59.490 104.925 ;
        RECT 64.380 104.675 66.485 104.925 ;
        RECT 67.065 104.675 69.170 104.925 ;
        RECT 74.060 104.675 76.165 104.925 ;
        RECT 76.745 104.675 78.850 104.925 ;
        RECT 83.740 104.675 85.845 104.925 ;
        RECT 86.425 104.675 88.530 104.925 ;
        RECT 93.420 104.675 98.210 104.925 ;
        RECT 37.230 104.145 37.520 104.625 ;
        RECT 38.915 104.145 39.205 104.625 ;
        RECT 45.910 104.145 46.245 104.675 ;
        RECT 48.635 104.145 48.925 104.675 ;
        RECT 55.610 104.145 55.900 104.675 ;
        RECT 58.315 104.145 58.605 104.675 ;
        RECT 65.245 104.145 65.535 104.675 ;
        RECT 67.970 104.145 68.260 104.675 ;
        RECT 74.930 104.145 75.220 104.675 ;
        RECT 77.655 104.145 77.945 104.675 ;
        RECT 84.665 104.145 84.955 104.675 ;
        RECT 87.335 104.145 87.625 104.675 ;
        RECT 94.300 104.145 94.590 104.675 ;
        RECT 97.035 104.145 97.325 104.675 ;
        RECT 103.075 104.625 105.970 104.975 ;
        RECT 104.035 104.145 104.325 104.625 ;
        RECT 105.680 104.145 105.970 104.625 ;
        RECT 37.230 103.830 105.970 104.145 ;
        RECT 35.370 78.565 106.215 86.010 ;
        RECT 35.370 74.300 42.980 78.565 ;
        RECT 43.510 74.825 46.560 77.875 ;
        RECT 49.950 74.825 53.000 77.875 ;
        RECT 56.390 74.825 59.440 77.875 ;
        RECT 62.830 74.825 65.880 77.875 ;
        RECT 69.270 74.825 72.320 77.875 ;
        RECT 75.710 74.825 78.760 77.875 ;
        RECT 82.150 74.825 85.200 77.875 ;
        RECT 88.590 74.825 91.640 77.875 ;
        RECT 95.030 74.825 98.080 77.875 ;
        RECT 35.370 67.870 49.445 74.300 ;
        RECT 49.950 68.385 53.000 71.435 ;
        RECT 56.390 68.385 59.440 71.435 ;
        RECT 62.830 68.385 65.880 71.435 ;
        RECT 69.270 68.385 72.320 71.435 ;
        RECT 75.710 68.385 78.760 71.435 ;
        RECT 82.150 68.385 85.200 71.435 ;
        RECT 88.590 68.385 91.640 71.435 ;
        RECT 95.030 68.385 98.080 71.435 ;
        RECT 100.415 67.870 106.215 78.565 ;
        RECT 18.465 60.955 19.375 61.185 ;
        RECT 18.810 60.585 19.040 60.955 ;
        RECT 17.860 60.245 20.290 60.585 ;
        RECT 35.370 60.250 106.215 67.870 ;
        RECT 109.990 65.855 110.220 172.770 ;
        RECT 114.830 162.875 115.060 173.425 ;
        RECT 110.760 162.645 119.740 162.875 ;
        RECT 114.830 152.095 115.060 162.645 ;
        RECT 110.760 151.865 119.740 152.095 ;
        RECT 114.830 141.315 115.060 151.865 ;
        RECT 110.760 141.085 119.740 141.315 ;
        RECT 114.830 130.535 115.060 141.085 ;
        RECT 110.760 130.305 119.740 130.535 ;
        RECT 114.830 119.755 115.060 130.305 ;
        RECT 110.760 119.525 119.740 119.755 ;
        RECT 114.830 108.975 115.060 119.525 ;
        RECT 110.760 108.745 119.740 108.975 ;
        RECT 114.830 98.195 115.060 108.745 ;
        RECT 110.760 97.965 119.740 98.195 ;
        RECT 114.830 87.415 115.060 97.965 ;
        RECT 110.760 87.185 119.740 87.415 ;
        RECT 114.830 76.635 115.060 87.185 ;
        RECT 110.760 76.405 119.740 76.635 ;
        RECT 120.280 65.855 120.510 172.770 ;
        RECT 109.450 65.505 121.050 65.855 ;
        RECT 35.370 59.850 134.130 60.250 ;
        RECT 17.680 54.910 134.130 59.850 ;
      LAYER met2 ;
        RECT 18.130 175.350 31.960 180.155 ;
        RECT 126.830 179.630 127.290 191.055 ;
        RECT 36.270 179.170 127.290 179.630 ;
        RECT 24.640 170.115 26.920 170.690 ;
        RECT 18.730 168.620 26.950 169.195 ;
        RECT 36.270 149.920 36.730 179.170 ;
        RECT 38.590 155.570 39.190 177.785 ;
        RECT 72.830 173.620 73.290 179.170 ;
        RECT 55.255 173.265 92.085 173.620 ;
        RECT 86.135 167.050 86.730 167.605 ;
        RECT 41.365 166.085 41.950 166.130 ;
        RECT 41.365 165.625 61.205 166.085 ;
        RECT 73.555 165.625 93.395 166.085 ;
        RECT 41.365 165.580 41.950 165.625 ;
        RECT 92.805 165.530 93.395 165.625 ;
        RECT 106.435 155.570 107.035 176.095 ;
        RECT 127.610 174.470 128.040 192.365 ;
        RECT 129.245 175.350 134.130 180.155 ;
        RECT 58.270 150.550 78.160 150.975 ;
        RECT 68.905 146.780 69.365 146.795 ;
        RECT 68.900 146.380 69.365 146.780 ;
        RECT 68.905 146.375 69.365 146.380 ;
        RECT 67.450 145.520 67.925 145.970 ;
        RECT 59.660 144.865 62.445 145.180 ;
        RECT 68.530 144.865 70.010 145.180 ;
        RECT 74.355 144.865 77.175 145.180 ;
        RECT 30.165 143.715 30.625 143.865 ;
        RECT 41.360 143.715 41.950 143.950 ;
        RECT 59.660 143.715 60.010 144.865 ;
        RECT 68.530 143.715 68.775 144.865 ;
        RECT 76.825 143.715 77.175 144.865 ;
        RECT 92.805 143.715 93.395 143.850 ;
        RECT 30.165 143.400 60.010 143.715 ;
        RECT 61.730 143.400 68.775 143.715 ;
        RECT 69.690 143.400 75.070 143.715 ;
        RECT 76.825 143.400 93.395 143.715 ;
        RECT 92.805 143.295 93.395 143.400 ;
        RECT 67.425 142.695 67.795 143.085 ;
        RECT 69.000 142.705 69.385 143.075 ;
        RECT 61.925 137.610 75.025 138.035 ;
        RECT 38.590 129.535 39.190 136.560 ;
        RECT 106.430 129.525 107.030 136.560 ;
        RECT 47.705 127.385 49.810 127.865 ;
        RECT 57.385 127.385 59.490 127.865 ;
        RECT 47.705 119.915 49.810 120.395 ;
        RECT 47.650 118.705 49.835 119.115 ;
        RECT 57.355 117.900 59.515 118.255 ;
        RECT 86.425 106.635 88.530 107.115 ;
        RECT 49.950 79.015 98.080 80.120 ;
        RECT 43.505 74.825 46.560 77.875 ;
        RECT 49.950 74.825 53.000 77.875 ;
        RECT 56.390 74.825 59.440 77.875 ;
        RECT 62.830 74.825 65.880 77.875 ;
        RECT 69.270 74.825 72.320 77.875 ;
        RECT 75.710 74.825 78.760 77.875 ;
        RECT 82.150 74.825 85.200 77.875 ;
        RECT 88.590 74.825 91.640 77.875 ;
        RECT 95.030 74.825 98.080 77.875 ;
        RECT 49.950 72.575 98.080 73.680 ;
        RECT 49.950 68.385 53.000 71.435 ;
        RECT 56.390 68.385 59.440 71.435 ;
        RECT 62.830 68.385 65.880 71.435 ;
        RECT 69.270 68.385 72.320 71.435 ;
        RECT 75.710 68.385 78.760 71.435 ;
        RECT 82.150 68.385 85.200 71.435 ;
        RECT 88.590 68.385 91.640 71.435 ;
        RECT 95.030 68.385 98.080 71.435 ;
        RECT 17.680 54.910 134.130 60.250 ;
      LAYER met3 ;
        RECT 1.000 175.390 134.130 180.155 ;
        RECT 26.320 168.620 26.920 170.690 ;
        RECT 86.135 167.050 109.610 167.605 ;
        RECT 41.365 87.250 41.950 166.130 ;
        RECT 68.100 150.470 68.715 151.010 ;
        RECT 67.385 146.380 69.350 146.780 ;
        RECT 67.450 145.535 69.415 145.955 ;
        RECT 67.385 142.660 67.835 144.755 ;
        RECT 68.965 142.680 69.415 145.535 ;
        RECT 68.165 137.590 68.715 138.035 ;
        RECT 92.805 133.850 93.395 166.085 ;
        RECT 47.675 133.260 93.395 133.850 ;
        RECT 47.675 127.385 49.835 133.260 ;
        RECT 57.355 130.045 109.610 130.595 ;
        RECT 57.355 127.385 59.515 130.045 ;
        RECT 44.925 119.915 49.835 120.395 ;
        RECT 44.925 94.870 47.145 119.915 ;
        RECT 47.655 119.085 49.830 119.110 ;
        RECT 47.655 118.725 49.835 119.085 ;
        RECT 47.655 118.715 49.830 118.725 ;
        RECT 57.335 117.870 59.520 119.255 ;
        RECT 86.350 94.870 88.595 107.115 ;
        RECT 44.925 93.270 68.175 94.870 ;
        RECT 43.510 77.875 46.560 87.615 ;
        RECT 43.505 74.825 46.560 77.875 ;
        RECT 49.950 74.825 53.000 80.120 ;
        RECT 56.390 74.825 59.440 80.120 ;
        RECT 62.830 74.825 65.880 80.120 ;
        RECT 67.025 79.015 68.175 93.270 ;
        RECT 73.380 93.270 88.595 94.870 ;
        RECT 69.270 74.825 72.320 80.120 ;
        RECT 49.950 68.385 53.000 73.680 ;
        RECT 56.390 68.385 59.440 73.680 ;
        RECT 62.830 68.385 65.880 73.680 ;
        RECT 69.270 68.385 72.320 73.680 ;
        RECT 73.380 72.575 74.530 93.270 ;
        RECT 75.710 74.825 78.760 80.120 ;
        RECT 82.150 74.825 85.200 80.120 ;
        RECT 88.590 74.825 91.640 80.120 ;
        RECT 95.030 74.825 98.080 80.120 ;
        RECT 75.710 68.385 78.760 73.680 ;
        RECT 82.150 68.385 85.200 73.680 ;
        RECT 88.590 68.385 91.640 73.680 ;
        RECT 95.030 68.385 98.080 73.680 ;
        RECT 3.985 54.925 134.115 59.880 ;
      LAYER met4 ;
        RECT 67.385 144.320 67.835 146.780 ;
        RECT 68.170 137.590 68.715 151.010 ;
        RECT 47.675 118.735 59.515 119.085 ;
        RECT 41.365 87.250 46.560 87.615 ;
        RECT 109.055 45.825 109.610 167.605 ;
        RECT 109.055 45.285 152.710 45.825 ;
        RECT 151.810 1.000 152.710 45.285 ;
  END
END tt_um_analog_ic_bg_26
END LIBRARY

